VERSION 5.7 ;
DIVIDERCHAR "/" ;
BUSBITCHARS "[]" ;

VERSION 5.7 ;

BUSBITCHARS "[]" ;
DIVIDERCHAR "/" ;

UNITS
  TIME NANOSECONDS 1 ;
  CAPACITANCE PICOFARADS 1 ;
  RESISTANCE OHMS 1 ;
  DATABASE MICRONS 1000 ;
END UNITS

MANUFACTURINGGRID 0.005 ;

PROPERTYDEFINITIONS
  LAYER LEF58_TYPE STRING ;
END PROPERTYDEFINITIONS

# High density, single height
SITE obssite
  SYMMETRY Y ;
  CLASS CORE ;
  SIZE 0.2 BY 3.2 ;
END obssite


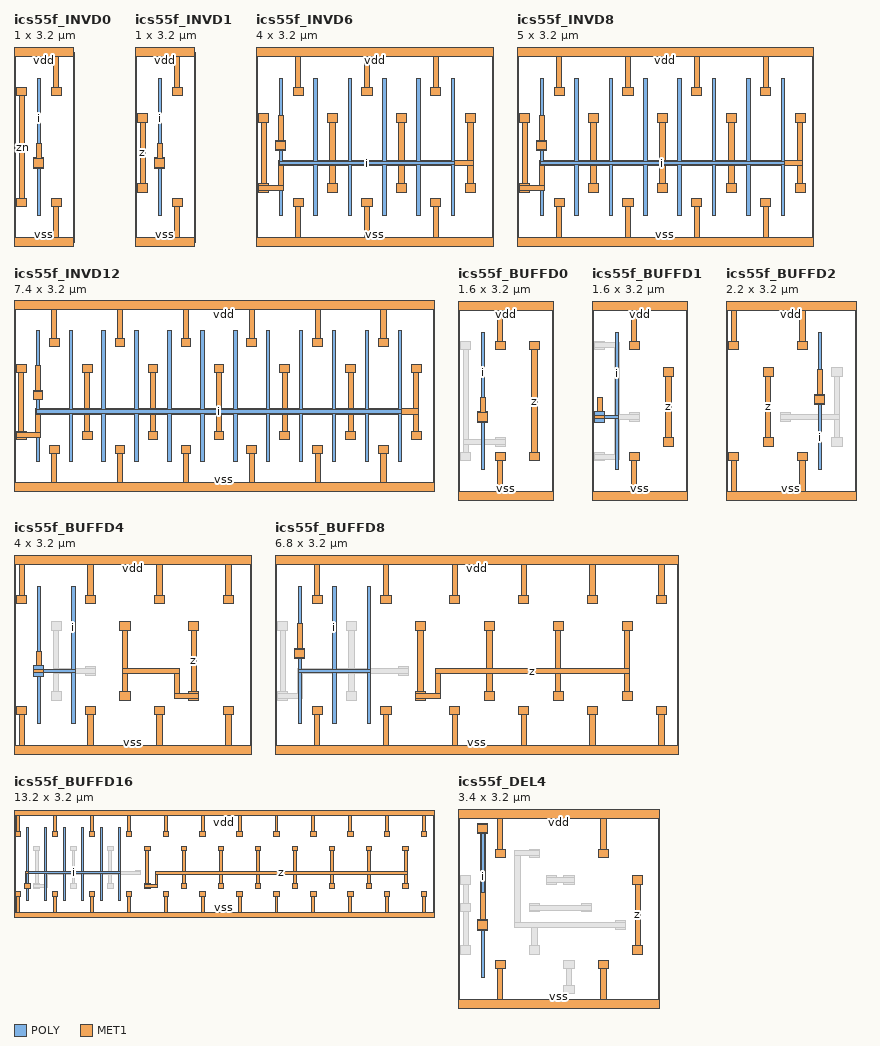
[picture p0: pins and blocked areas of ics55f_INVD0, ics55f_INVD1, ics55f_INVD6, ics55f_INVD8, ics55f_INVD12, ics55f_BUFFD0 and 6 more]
MACRO ics55f_INVD0
  CLASS CORE ;
  FOREIGN ics55f_INVD0 ;
  ORIGIN 0.000 0.000 ;
  SIZE 1.000 BY 3.200 ;
  SYMMETRY X Y R90 ;
  SITE obssite ;
  PIN i
    DIRECTION INPUT ;
    USE SIGNAL ;
    ANTENNAGATEAREA 0.030000 ;
    PORT
      LAYER POLY ;
        RECT 0.390 0.445 0.450 1.245 ;
        RECT 0.335 1.245 0.505 1.415 ;
        RECT 0.390 1.415 0.450 2.755 ;
      LAYER MET1 ;
        RECT 0.335 1.260 0.505 1.400 ;
        RECT 0.375 1.400 0.465 1.665 ;
    END
  END i
  PIN vdd
    DIRECTION INOUT ;
    USE POWER ;
    SHAPE ABUTMENT ;
    PORT
      LAYER MET1 ;
        RECT 0.625 2.470 0.795 2.610 ;
        RECT 0.665 2.610 0.755 3.120 ;
        RECT 0.000 3.120 1.000 3.280 ;
    END
  END vdd
  PIN vss
    DIRECTION INOUT ;
    USE GROUND ;
    SHAPE ABUTMENT ;
    PORT
      LAYER MET1 ;
        RECT 0.000 -0.080 1.000 0.080 ;
        RECT 0.665 0.080 0.755 0.590 ;
        RECT 0.625 0.590 0.795 0.730 ;
    END
  END vss
  PIN zn
    DIRECTION OUTPUT ;
    USE SIGNAL ;
    ANTENNADIFFAREA 0.167500 ;
    PORT
      LAYER MET1 ;
        RECT 0.045 0.590 0.215 0.730 ;
        RECT 0.085 0.730 0.175 2.470 ;
        RECT 0.045 2.470 0.215 2.610 ;
    END
  END zn
END ics55f_INVD0

MACRO ics55f_INVD1
  CLASS CORE ;
  FOREIGN ics55f_INVD1 ;
  ORIGIN 0.000 0.000 ;
  SIZE 1.000 BY 3.200 ;
  SYMMETRY X Y R90 ;
  SITE obssite ;
  PIN z
    DIRECTION OUTPUT ;
    USE SIGNAL ;
    ANTENNADIFFAREA 0.335000 ;
    PORT
      LAYER MET1 ;
        RECT 0.045 0.840 0.215 0.980 ;
        RECT 0.085 0.980 0.175 2.020 ;
        RECT 0.045 2.020 0.215 2.160 ;
    END
  END z
  PIN vdd
    DIRECTION INOUT ;
    USE POWER ;
    SHAPE ABUTMENT ;
    PORT
      LAYER MET1 ;
        RECT 0.625 2.470 0.795 2.610 ;
        RECT 0.665 2.610 0.755 3.120 ;
        RECT 0.000 3.120 1.000 3.280 ;
    END
  END vdd
  PIN vss
    DIRECTION INOUT ;
    USE GROUND ;
    SHAPE ABUTMENT ;
    PORT
      LAYER MET1 ;
        RECT 0.000 -0.080 1.000 0.080 ;
        RECT 0.665 0.080 0.755 0.590 ;
        RECT 0.625 0.590 0.795 0.730 ;
    END
  END vss
  PIN i
    DIRECTION INPUT ;
    USE SIGNAL ;
    ANTENNAGATEAREA 0.060000 ;
    PORT
      LAYER POLY ;
        RECT 0.390 0.445 0.450 1.245 ;
        RECT 0.335 1.245 0.505 1.415 ;
        RECT 0.390 1.415 0.450 2.755 ;
      LAYER MET1 ;
        RECT 0.335 1.260 0.505 1.400 ;
        RECT 0.375 1.400 0.465 1.665 ;
    END
  END i
END ics55f_INVD1

MACRO ics55f_INVD6
  CLASS CORE ;
  FOREIGN ics55f_INVD6 ;
  ORIGIN 0.000 0.000 ;
  SIZE 4.000 BY 3.200 ;
  SYMMETRY X Y R90 ;
  SITE obssite ;
  PIN i
    DIRECTION INPUT ;
    USE SIGNAL ;
    ANTENNAGATEAREA 0.360000 ;
    PORT
      LAYER POLY ;
        RECT 0.390 0.445 0.450 1.300 ;
        RECT 0.970 0.445 1.030 1.300 ;
        RECT 1.550 0.445 1.610 1.300 ;
        RECT 2.130 0.445 2.190 1.300 ;
        RECT 2.710 0.445 2.770 1.300 ;
        RECT 3.290 0.445 3.350 1.300 ;
        RECT 0.390 1.300 3.350 1.360 ;
        RECT 0.390 1.360 0.450 1.535 ;
        RECT 0.970 1.360 1.030 2.755 ;
        RECT 1.550 1.360 1.610 2.755 ;
        RECT 2.130 1.360 2.190 2.755 ;
        RECT 2.710 1.360 2.770 2.755 ;
        RECT 3.290 1.360 3.350 2.755 ;
        RECT 0.335 1.535 0.505 1.705 ;
        RECT 0.390 1.705 0.450 2.755 ;
      LAYER MET1 ;
        RECT 0.335 1.550 0.505 1.690 ;
        RECT 0.375 1.690 0.465 2.135 ;
    END
  END i
  PIN vdd
    DIRECTION INOUT ;
    USE POWER ;
    SHAPE ABUTMENT ;
    PORT
      LAYER MET1 ;
        RECT 0.625 2.470 0.795 2.610 ;
        RECT 1.785 2.470 1.955 2.610 ;
        RECT 2.945 2.470 3.115 2.610 ;
        RECT 0.665 2.610 0.755 3.120 ;
        RECT 1.825 2.610 1.915 3.120 ;
        RECT 2.985 2.610 3.075 3.120 ;
        RECT 0.000 3.120 4.000 3.280 ;
    END
  END vdd
  PIN vss
    DIRECTION INOUT ;
    USE GROUND ;
    SHAPE ABUTMENT ;
    PORT
      LAYER MET1 ;
        RECT 0.000 -0.080 4.000 0.080 ;
        RECT 0.665 0.080 0.755 0.590 ;
        RECT 1.825 0.080 1.915 0.590 ;
        RECT 2.985 0.080 3.075 0.590 ;
        RECT 0.625 0.590 0.795 0.730 ;
        RECT 1.785 0.590 1.955 0.730 ;
        RECT 2.945 0.590 3.115 0.730 ;
    END
  END vss
  PIN zn
    DIRECTION OUTPUT ;
    USE SIGNAL ;
    ANTENNADIFFAREA 1.710000 ;
    PORT
      LAYER MET1 ;
        RECT 0.045 0.840 0.215 0.865 ;
        RECT 1.205 0.840 1.375 0.980 ;
        RECT 2.365 0.840 2.535 0.980 ;
        RECT 3.525 0.840 3.695 0.980 ;
        RECT 0.045 0.865 0.465 0.955 ;
        RECT 0.045 0.955 0.215 0.980 ;
        RECT 0.375 0.955 0.465 1.285 ;
        RECT 0.085 0.980 0.175 2.020 ;
        RECT 1.245 0.980 1.335 1.285 ;
        RECT 2.405 0.980 2.495 1.285 ;
        RECT 3.565 0.980 3.655 1.285 ;
        RECT 0.375 1.285 3.655 1.375 ;
        RECT 1.245 1.375 1.335 2.020 ;
        RECT 2.405 1.375 2.495 2.020 ;
        RECT 3.565 1.375 3.655 2.020 ;
        RECT 0.045 2.020 0.215 2.160 ;
        RECT 1.205 2.020 1.375 2.160 ;
        RECT 2.365 2.020 2.535 2.160 ;
        RECT 3.525 2.020 3.695 2.160 ;
    END
  END zn
END ics55f_INVD6

MACRO ics55f_INVD8
  CLASS CORE ;
  FOREIGN ics55f_INVD8 ;
  ORIGIN 0.000 0.000 ;
  SIZE 5.000 BY 3.200 ;
  SYMMETRY X Y R90 ;
  SITE obssite ;
  PIN i
    DIRECTION INPUT ;
    USE SIGNAL ;
    ANTENNAGATEAREA 0.480000 ;
    PORT
      LAYER POLY ;
        RECT 0.390 0.445 0.450 1.300 ;
        RECT 0.970 0.445 1.030 1.300 ;
        RECT 1.550 0.445 1.610 1.300 ;
        RECT 2.130 0.445 2.190 1.300 ;
        RECT 2.710 0.445 2.770 1.300 ;
        RECT 3.290 0.445 3.350 1.300 ;
        RECT 3.870 0.445 3.930 1.300 ;
        RECT 4.450 0.445 4.510 1.300 ;
        RECT 0.390 1.300 4.510 1.360 ;
        RECT 0.390 1.360 0.450 1.535 ;
        RECT 0.970 1.360 1.030 2.755 ;
        RECT 1.550 1.360 1.610 2.755 ;
        RECT 2.130 1.360 2.190 2.755 ;
        RECT 2.710 1.360 2.770 2.755 ;
        RECT 3.290 1.360 3.350 2.755 ;
        RECT 3.870 1.360 3.930 2.755 ;
        RECT 4.450 1.360 4.510 2.755 ;
        RECT 0.335 1.535 0.505 1.705 ;
        RECT 0.390 1.705 0.450 2.755 ;
      LAYER MET1 ;
        RECT 0.335 1.550 0.505 1.690 ;
        RECT 0.375 1.690 0.465 2.135 ;
    END
  END i
  PIN vdd
    DIRECTION INOUT ;
    USE POWER ;
    SHAPE ABUTMENT ;
    PORT
      LAYER MET1 ;
        RECT 0.625 2.470 0.795 2.610 ;
        RECT 1.785 2.470 1.955 2.610 ;
        RECT 2.945 2.470 3.115 2.610 ;
        RECT 4.105 2.470 4.275 2.610 ;
        RECT 0.665 2.610 0.755 3.120 ;
        RECT 1.825 2.610 1.915 3.120 ;
        RECT 2.985 2.610 3.075 3.120 ;
        RECT 4.145 2.610 4.235 3.120 ;
        RECT 0.000 3.120 5.000 3.280 ;
    END
  END vdd
  PIN vss
    DIRECTION INOUT ;
    USE GROUND ;
    SHAPE ABUTMENT ;
    PORT
      LAYER MET1 ;
        RECT 0.000 -0.080 5.000 0.080 ;
        RECT 0.665 0.080 0.755 0.590 ;
        RECT 1.825 0.080 1.915 0.590 ;
        RECT 2.985 0.080 3.075 0.590 ;
        RECT 4.145 0.080 4.235 0.590 ;
        RECT 0.625 0.590 0.795 0.730 ;
        RECT 1.785 0.590 1.955 0.730 ;
        RECT 2.945 0.590 3.115 0.730 ;
        RECT 4.105 0.590 4.275 0.730 ;
    END
  END vss
  PIN zn
    DIRECTION OUTPUT ;
    USE SIGNAL ;
    ANTENNADIFFAREA 2.230000 ;
    PORT
      LAYER MET1 ;
        RECT 0.045 0.840 0.215 0.865 ;
        RECT 1.205 0.840 1.375 0.980 ;
        RECT 2.365 0.840 2.535 0.980 ;
        RECT 3.525 0.840 3.695 0.980 ;
        RECT 4.685 0.840 4.855 0.980 ;
        RECT 0.045 0.865 0.465 0.955 ;
        RECT 0.045 0.955 0.215 0.980 ;
        RECT 0.375 0.955 0.465 1.285 ;
        RECT 0.085 0.980 0.175 2.020 ;
        RECT 1.245 0.980 1.335 1.285 ;
        RECT 2.405 0.980 2.495 1.285 ;
        RECT 3.565 0.980 3.655 1.285 ;
        RECT 4.725 0.980 4.815 1.285 ;
        RECT 0.375 1.285 4.815 1.375 ;
        RECT 1.245 1.375 1.335 2.020 ;
        RECT 2.405 1.375 2.495 2.020 ;
        RECT 3.565 1.375 3.655 2.020 ;
        RECT 4.725 1.375 4.815 2.020 ;
        RECT 0.045 2.020 0.215 2.160 ;
        RECT 1.205 2.020 1.375 2.160 ;
        RECT 2.365 2.020 2.535 2.160 ;
        RECT 3.525 2.020 3.695 2.160 ;
        RECT 4.685 2.020 4.855 2.160 ;
    END
  END zn
END ics55f_INVD8

MACRO ics55f_INVD12
  CLASS CORE ;
  FOREIGN ics55f_INVD12 ;
  ORIGIN 0.000 0.000 ;
  SIZE 7.400 BY 3.200 ;
  SYMMETRY X Y R90 ;
  SITE obssite ;
  PIN i
    DIRECTION INPUT ;
    USE SIGNAL ;
    ANTENNAGATEAREA 0.720000 ;
    PORT
      LAYER POLY ;
        RECT 0.390 0.445 0.450 1.300 ;
        RECT 0.970 0.445 1.030 1.300 ;
        RECT 1.550 0.445 1.610 1.300 ;
        RECT 2.130 0.445 2.190 1.300 ;
        RECT 2.710 0.445 2.770 1.300 ;
        RECT 3.290 0.445 3.350 1.300 ;
        RECT 3.870 0.445 3.930 1.300 ;
        RECT 4.450 0.445 4.510 1.300 ;
        RECT 5.030 0.445 5.090 1.300 ;
        RECT 5.610 0.445 5.670 1.300 ;
        RECT 6.190 0.445 6.250 1.300 ;
        RECT 6.770 0.445 6.830 1.300 ;
        RECT 0.390 1.300 6.830 1.360 ;
        RECT 0.390 1.360 0.450 1.535 ;
        RECT 0.970 1.360 1.030 2.755 ;
        RECT 1.550 1.360 1.610 2.755 ;
        RECT 2.130 1.360 2.190 2.755 ;
        RECT 2.710 1.360 2.770 2.755 ;
        RECT 3.290 1.360 3.350 2.755 ;
        RECT 3.870 1.360 3.930 2.755 ;
        RECT 4.450 1.360 4.510 2.755 ;
        RECT 5.030 1.360 5.090 2.755 ;
        RECT 5.610 1.360 5.670 2.755 ;
        RECT 6.190 1.360 6.250 2.755 ;
        RECT 6.770 1.360 6.830 2.755 ;
        RECT 0.335 1.535 0.505 1.705 ;
        RECT 0.390 1.705 0.450 2.755 ;
      LAYER MET1 ;
        RECT 0.335 1.550 0.505 1.690 ;
        RECT 0.375 1.690 0.465 2.135 ;
    END
  END i
  PIN vdd
    DIRECTION INOUT ;
    USE POWER ;
    SHAPE ABUTMENT ;
    PORT
      LAYER MET1 ;
        RECT 0.625 2.470 0.795 2.610 ;
        RECT 1.785 2.470 1.955 2.610 ;
        RECT 2.945 2.470 3.115 2.610 ;
        RECT 4.105 2.470 4.275 2.610 ;
        RECT 5.265 2.470 5.435 2.610 ;
        RECT 6.425 2.470 6.595 2.610 ;
        RECT 0.665 2.610 0.755 3.120 ;
        RECT 1.825 2.610 1.915 3.120 ;
        RECT 2.985 2.610 3.075 3.120 ;
        RECT 4.145 2.610 4.235 3.120 ;
        RECT 5.305 2.610 5.395 3.120 ;
        RECT 6.465 2.610 6.555 3.120 ;
        RECT 0.000 3.120 7.400 3.280 ;
    END
  END vdd
  PIN vss
    DIRECTION INOUT ;
    USE GROUND ;
    SHAPE ABUTMENT ;
    PORT
      LAYER MET1 ;
        RECT 0.000 -0.080 7.400 0.080 ;
        RECT 0.665 0.080 0.755 0.590 ;
        RECT 1.825 0.080 1.915 0.590 ;
        RECT 2.985 0.080 3.075 0.590 ;
        RECT 4.145 0.080 4.235 0.590 ;
        RECT 5.305 0.080 5.395 0.590 ;
        RECT 6.465 0.080 6.555 0.590 ;
        RECT 0.625 0.590 0.795 0.730 ;
        RECT 1.785 0.590 1.955 0.730 ;
        RECT 2.945 0.590 3.115 0.730 ;
        RECT 4.105 0.590 4.275 0.730 ;
        RECT 5.265 0.590 5.435 0.730 ;
        RECT 6.425 0.590 6.595 0.730 ;
    END
  END vss
  PIN zn
    DIRECTION OUTPUT ;
    USE SIGNAL ;
    ANTENNADIFFAREA 3.270000 ;
    PORT
      LAYER MET1 ;
        RECT 0.045 0.840 0.215 0.865 ;
        RECT 1.205 0.840 1.375 0.980 ;
        RECT 2.365 0.840 2.535 0.980 ;
        RECT 3.525 0.840 3.695 0.980 ;
        RECT 4.685 0.840 4.855 0.980 ;
        RECT 5.845 0.840 6.015 0.980 ;
        RECT 7.005 0.840 7.175 0.980 ;
        RECT 0.045 0.865 0.465 0.955 ;
        RECT 0.045 0.955 0.215 0.980 ;
        RECT 0.375 0.955 0.465 1.285 ;
        RECT 0.085 0.980 0.175 2.020 ;
        RECT 1.245 0.980 1.335 1.285 ;
        RECT 2.405 0.980 2.495 1.285 ;
        RECT 3.565 0.980 3.655 1.285 ;
        RECT 4.725 0.980 4.815 1.285 ;
        RECT 5.885 0.980 5.975 1.285 ;
        RECT 7.045 0.980 7.135 1.285 ;
        RECT 0.375 1.285 7.135 1.375 ;
        RECT 1.245 1.375 1.335 2.020 ;
        RECT 2.405 1.375 2.495 2.020 ;
        RECT 3.565 1.375 3.655 2.020 ;
        RECT 4.725 1.375 4.815 2.020 ;
        RECT 5.885 1.375 5.975 2.020 ;
        RECT 7.045 1.375 7.135 2.020 ;
        RECT 0.045 2.020 0.215 2.160 ;
        RECT 1.205 2.020 1.375 2.160 ;
        RECT 2.365 2.020 2.535 2.160 ;
        RECT 3.525 2.020 3.695 2.160 ;
        RECT 4.685 2.020 4.855 2.160 ;
        RECT 5.845 2.020 6.015 2.160 ;
        RECT 7.005 2.020 7.175 2.160 ;
    END
  END zn
END ics55f_INVD12

MACRO ics55f_BUFFD0
  CLASS CORE ;
  FOREIGN ics55f_BUFFD0 ;
  ORIGIN 0.000 0.000 ;
  SIZE 1.600 BY 3.200 ;
  SYMMETRY X Y R90 ;
  SITE obssite ;
  PIN i
    DIRECTION INPUT ;
    USE SIGNAL ;
    ANTENNAGATEAREA 0.018900 ;
    PORT
      LAYER POLY ;
        RECT 0.390 0.445 0.450 1.245 ;
        RECT 0.335 1.245 0.505 1.415 ;
        RECT 0.390 1.415 0.450 2.755 ;
      LAYER MET1 ;
        RECT 0.335 1.260 0.505 1.400 ;
        RECT 0.375 1.400 0.465 1.665 ;
    END
  END i
  PIN vdd
    DIRECTION INOUT ;
    USE POWER ;
    SHAPE ABUTMENT ;
    PORT
      LAYER MET1 ;
        RECT 0.625 2.470 0.795 2.610 ;
        RECT 0.665 2.610 0.755 3.120 ;
        RECT 0.000 3.120 1.600 3.280 ;
    END
  END vdd
  PIN vss
    DIRECTION INOUT ;
    USE GROUND ;
    SHAPE ABUTMENT ;
    PORT
      LAYER MET1 ;
        RECT 0.000 -0.080 1.600 0.080 ;
        RECT 0.665 0.080 0.755 0.590 ;
        RECT 0.625 0.590 0.795 0.730 ;
    END
  END vss
  PIN z
    DIRECTION OUTPUT ;
    USE SIGNAL ;
    ANTENNADIFFAREA 0.147225 ;
    PORT
      LAYER MET1 ;
        RECT 1.205 0.590 1.375 0.730 ;
        RECT 1.245 0.730 1.335 2.470 ;
        RECT 1.205 2.470 1.375 2.610 ;
    END
  END z
  OBS
    LAYER MET1 ;
      RECT 0.045 0.590 0.215 0.730 ;
      RECT 0.085 0.730 0.175 0.865 ;
      RECT 0.625 0.840 0.795 0.865 ;
      RECT 0.085 0.865 0.795 0.955 ;
      RECT 0.085 0.955 0.175 2.470 ;
      RECT 0.625 0.955 0.795 0.980 ;
      RECT 0.045 2.470 0.215 2.610 ;
  END
END ics55f_BUFFD0

MACRO ics55f_BUFFD1
  CLASS CORE ;
  FOREIGN ics55f_BUFFD1 ;
  ORIGIN 0.000 0.000 ;
  SIZE 1.600 BY 3.200 ;
  SYMMETRY X Y R90 ;
  SITE obssite ;
  PIN i
    DIRECTION INPUT ;
    USE SIGNAL ;
    ANTENNAGATEAREA 0.030000 ;
    PORT
      LAYER POLY ;
        RECT 0.390 0.445 0.450 1.300 ;
        RECT 0.045 1.245 0.215 1.300 ;
        RECT 0.045 1.300 0.450 1.360 ;
        RECT 0.045 1.360 0.215 1.415 ;
        RECT 0.390 1.360 0.450 2.755 ;
      LAYER MET1 ;
        RECT 0.045 1.260 0.215 1.400 ;
        RECT 0.085 1.400 0.175 1.665 ;
    END
  END i
  PIN vdd
    DIRECTION INOUT ;
    USE POWER ;
    SHAPE ABUTMENT ;
    PORT
      LAYER MET1 ;
        RECT 0.625 2.470 0.795 2.610 ;
        RECT 0.665 2.610 0.755 3.120 ;
        RECT 0.000 3.120 1.600 3.280 ;
    END
  END vdd
  PIN vss
    DIRECTION INOUT ;
    USE GROUND ;
    SHAPE ABUTMENT ;
    PORT
      LAYER MET1 ;
        RECT 0.000 -0.080 1.600 0.080 ;
        RECT 0.665 0.080 0.755 0.590 ;
        RECT 0.625 0.590 0.795 0.730 ;
    END
  END vss
  PIN z
    DIRECTION OUTPUT ;
    USE SIGNAL ;
    ANTENNADIFFAREA 0.335000 ;
    PORT
      LAYER MET1 ;
        RECT 1.205 0.840 1.375 0.980 ;
        RECT 1.245 0.980 1.335 2.020 ;
        RECT 1.205 2.020 1.375 2.160 ;
    END
  END z
  OBS
    LAYER MET1 ;
      RECT 0.045 0.590 0.215 0.615 ;
      RECT 0.045 0.615 0.465 0.705 ;
      RECT 0.045 0.705 0.215 0.730 ;
      RECT 0.375 0.705 0.465 1.285 ;
      RECT 0.625 1.260 0.795 1.285 ;
      RECT 0.375 1.285 0.795 1.375 ;
      RECT 0.375 1.375 0.465 2.495 ;
      RECT 0.625 1.375 0.795 1.400 ;
      RECT 0.045 2.470 0.215 2.495 ;
      RECT 0.045 2.495 0.465 2.585 ;
      RECT 0.045 2.585 0.215 2.610 ;
  END
END ics55f_BUFFD1

MACRO ics55f_BUFFD2
  CLASS CORE ;
  FOREIGN ics55f_BUFFD2 ;
  ORIGIN 0.000 0.000 ;
  SIZE 2.200 BY 3.200 ;
  SYMMETRY X Y R90 ;
  SITE obssite ;
  PIN i
    DIRECTION INPUT ;
    USE SIGNAL ;
    ANTENNAGATEAREA 0.060000 ;
    PORT
      LAYER POLY ;
        RECT 1.550 0.445 1.610 1.535 ;
        RECT 1.495 1.535 1.665 1.705 ;
        RECT 1.550 1.705 1.610 2.755 ;
      LAYER MET1 ;
        RECT 1.495 1.550 1.665 1.690 ;
        RECT 1.535 1.690 1.625 2.135 ;
    END
  END i
  PIN vdd
    DIRECTION INOUT ;
    USE POWER ;
    SHAPE ABUTMENT ;
    PORT
      LAYER MET1 ;
        RECT 0.045 2.470 0.215 2.610 ;
        RECT 1.205 2.470 1.375 2.610 ;
        RECT 0.085 2.610 0.175 3.120 ;
        RECT 1.245 2.610 1.335 3.120 ;
        RECT 0.000 3.120 2.200 3.280 ;
    END
  END vdd
  PIN vss
    DIRECTION INOUT ;
    USE GROUND ;
    SHAPE ABUTMENT ;
    PORT
      LAYER MET1 ;
        RECT 0.000 -0.080 2.200 0.080 ;
        RECT 0.085 0.080 0.175 0.590 ;
        RECT 1.245 0.080 1.335 0.590 ;
        RECT 0.045 0.590 0.215 0.730 ;
        RECT 1.205 0.590 1.375 0.730 ;
    END
  END vss
  PIN z
    DIRECTION OUTPUT ;
    USE SIGNAL ;
    ANTENNADIFFAREA 0.520000 ;
    PORT
      LAYER MET1 ;
        RECT 0.625 0.840 0.795 0.980 ;
        RECT 0.665 0.980 0.755 2.020 ;
        RECT 0.625 2.020 0.795 2.160 ;
    END
  END z
  OBS
    LAYER MET1 ;
      RECT 1.785 0.840 1.955 0.980 ;
      RECT 1.825 0.980 1.915 1.285 ;
      RECT 0.915 1.260 1.085 1.285 ;
      RECT 0.915 1.285 1.915 1.375 ;
      RECT 0.915 1.375 1.085 1.400 ;
      RECT 1.825 1.375 1.915 2.020 ;
      RECT 1.785 2.020 1.955 2.160 ;
  END
END ics55f_BUFFD2

MACRO ics55f_BUFFD4
  CLASS CORE ;
  FOREIGN ics55f_BUFFD4 ;
  ORIGIN 0.000 0.000 ;
  SIZE 4.000 BY 3.200 ;
  SYMMETRY X Y R90 ;
  SITE obssite ;
  PIN i
    DIRECTION INPUT ;
    USE SIGNAL ;
    ANTENNAGATEAREA 0.120000 ;
    PORT
      LAYER POLY ;
        RECT 0.390 0.445 0.450 1.245 ;
        RECT 0.970 0.445 1.030 1.300 ;
        RECT 0.335 1.245 0.505 1.300 ;
        RECT 0.335 1.300 1.030 1.360 ;
        RECT 0.335 1.360 0.505 1.415 ;
        RECT 0.970 1.360 1.030 2.755 ;
        RECT 0.390 1.415 0.450 2.755 ;
      LAYER MET1 ;
        RECT 0.335 1.260 0.505 1.400 ;
        RECT 0.375 1.400 0.465 1.665 ;
    END
  END i
  PIN vdd
    DIRECTION INOUT ;
    USE POWER ;
    SHAPE ABUTMENT ;
    PORT
      LAYER MET1 ;
        RECT 0.045 2.470 0.215 2.610 ;
        RECT 1.205 2.470 1.375 2.610 ;
        RECT 2.365 2.470 2.535 2.610 ;
        RECT 3.525 2.470 3.695 2.610 ;
        RECT 0.085 2.610 0.175 3.120 ;
        RECT 1.245 2.610 1.335 3.120 ;
        RECT 2.405 2.610 2.495 3.120 ;
        RECT 3.565 2.610 3.655 3.120 ;
        RECT 0.000 3.120 4.000 3.280 ;
    END
  END vdd
  PIN vss
    DIRECTION INOUT ;
    USE GROUND ;
    SHAPE ABUTMENT ;
    PORT
      LAYER MET1 ;
        RECT 0.000 -0.080 4.000 0.080 ;
        RECT 0.085 0.080 0.175 0.590 ;
        RECT 1.245 0.080 1.335 0.590 ;
        RECT 2.405 0.080 2.495 0.590 ;
        RECT 3.565 0.080 3.655 0.590 ;
        RECT 0.045 0.590 0.215 0.730 ;
        RECT 1.205 0.590 1.375 0.730 ;
        RECT 2.365 0.590 2.535 0.730 ;
        RECT 3.525 0.590 3.695 0.730 ;
    END
  END vss
  PIN z
    DIRECTION OUTPUT ;
    USE SIGNAL ;
    ANTENNADIFFAREA 1.040000 ;
    PORT
      LAYER MET1 ;
        RECT 1.785 0.840 1.955 0.980 ;
        RECT 2.945 0.840 3.115 0.865 ;
        RECT 2.695 0.865 3.115 0.955 ;
        RECT 2.695 0.955 2.785 1.285 ;
        RECT 2.945 0.955 3.115 0.980 ;
        RECT 1.825 0.980 1.915 1.285 ;
        RECT 2.985 0.980 3.075 2.020 ;
        RECT 1.825 1.285 2.785 1.375 ;
        RECT 1.825 1.375 1.915 2.020 ;
        RECT 1.785 2.020 1.955 2.160 ;
        RECT 2.945 2.020 3.115 2.160 ;
    END
  END z
  OBS
    LAYER MET1 ;
      RECT 0.625 0.840 0.795 0.980 ;
      RECT 0.665 0.980 0.755 1.285 ;
      RECT 1.205 1.260 1.375 1.285 ;
      RECT 0.665 1.285 1.375 1.375 ;
      RECT 0.665 1.375 0.755 2.020 ;
      RECT 1.205 1.375 1.375 1.400 ;
      RECT 0.625 2.020 0.795 2.160 ;
  END
END ics55f_BUFFD4

MACRO ics55f_BUFFD8
  CLASS CORE ;
  FOREIGN ics55f_BUFFD8 ;
  ORIGIN 0.000 0.000 ;
  SIZE 6.800 BY 3.200 ;
  SYMMETRY X Y R90 ;
  SITE obssite ;
  PIN i
    DIRECTION INPUT ;
    USE SIGNAL ;
    ANTENNAGATEAREA 0.160200 ;
    PORT
      LAYER POLY ;
        RECT 0.390 0.445 0.450 1.300 ;
        RECT 0.970 0.445 1.030 1.300 ;
        RECT 1.550 0.445 1.610 1.300 ;
        RECT 0.390 1.300 1.610 1.360 ;
        RECT 0.390 1.360 0.450 1.535 ;
        RECT 0.970 1.360 1.030 2.755 ;
        RECT 1.550 1.360 1.610 2.755 ;
        RECT 0.335 1.535 0.505 1.705 ;
        RECT 0.390 1.705 0.450 2.755 ;
      LAYER MET1 ;
        RECT 0.335 1.550 0.505 1.690 ;
        RECT 0.375 1.690 0.465 2.135 ;
    END
  END i
  PIN vdd
    DIRECTION INOUT ;
    USE POWER ;
    SHAPE ABUTMENT ;
    PORT
      LAYER MET1 ;
        RECT 0.625 2.470 0.795 2.610 ;
        RECT 1.785 2.470 1.955 2.610 ;
        RECT 2.945 2.470 3.115 2.610 ;
        RECT 4.105 2.470 4.275 2.610 ;
        RECT 5.265 2.470 5.435 2.610 ;
        RECT 6.425 2.470 6.595 2.610 ;
        RECT 0.665 2.610 0.755 3.120 ;
        RECT 1.825 2.610 1.915 3.120 ;
        RECT 2.985 2.610 3.075 3.120 ;
        RECT 4.145 2.610 4.235 3.120 ;
        RECT 5.305 2.610 5.395 3.120 ;
        RECT 6.465 2.610 6.555 3.120 ;
        RECT 0.000 3.120 6.800 3.280 ;
    END
  END vdd
  PIN vss
    DIRECTION INOUT ;
    USE GROUND ;
    SHAPE ABUTMENT ;
    PORT
      LAYER MET1 ;
        RECT 0.000 -0.080 6.800 0.080 ;
        RECT 0.665 0.080 0.755 0.590 ;
        RECT 1.825 0.080 1.915 0.590 ;
        RECT 2.985 0.080 3.075 0.590 ;
        RECT 4.145 0.080 4.235 0.590 ;
        RECT 5.305 0.080 5.395 0.590 ;
        RECT 6.465 0.080 6.555 0.590 ;
        RECT 0.625 0.590 0.795 0.730 ;
        RECT 1.785 0.590 1.955 0.730 ;
        RECT 2.945 0.590 3.115 0.730 ;
        RECT 4.105 0.590 4.275 0.730 ;
        RECT 5.265 0.590 5.435 0.730 ;
        RECT 6.425 0.590 6.595 0.730 ;
    END
  END vss
  PIN z
    DIRECTION OUTPUT ;
    USE SIGNAL ;
    ANTENNADIFFAREA 2.080000 ;
    PORT
      LAYER MET1 ;
        RECT 2.365 0.840 2.535 0.865 ;
        RECT 3.525 0.840 3.695 0.980 ;
        RECT 4.685 0.840 4.855 0.980 ;
        RECT 5.845 0.840 6.015 0.980 ;
        RECT 2.365 0.865 2.785 0.955 ;
        RECT 2.365 0.955 2.535 0.980 ;
        RECT 2.695 0.955 2.785 1.285 ;
        RECT 2.405 0.980 2.495 2.020 ;
        RECT 3.565 0.980 3.655 1.285 ;
        RECT 4.725 0.980 4.815 1.285 ;
        RECT 5.885 0.980 5.975 1.285 ;
        RECT 2.695 1.285 5.975 1.375 ;
        RECT 3.565 1.375 3.655 2.020 ;
        RECT 4.725 1.375 4.815 2.020 ;
        RECT 5.885 1.375 5.975 2.020 ;
        RECT 2.365 2.020 2.535 2.160 ;
        RECT 3.525 2.020 3.695 2.160 ;
        RECT 4.685 2.020 4.855 2.160 ;
        RECT 5.845 2.020 6.015 2.160 ;
    END
  END z
  OBS
    LAYER MET1 ;
      RECT 0.045 0.840 0.215 0.865 ;
      RECT 1.205 0.840 1.375 0.980 ;
      RECT 0.045 0.865 0.465 0.955 ;
      RECT 0.045 0.955 0.215 0.980 ;
      RECT 0.375 0.955 0.465 1.285 ;
      RECT 0.085 0.980 0.175 2.020 ;
      RECT 1.245 0.980 1.335 1.285 ;
      RECT 2.075 1.260 2.245 1.285 ;
      RECT 0.375 1.285 2.245 1.375 ;
      RECT 1.245 1.375 1.335 2.020 ;
      RECT 2.075 1.375 2.245 1.400 ;
      RECT 0.045 2.020 0.215 2.160 ;
      RECT 1.205 2.020 1.375 2.160 ;
  END
END ics55f_BUFFD8

MACRO ics55f_BUFFD16
  CLASS CORE ;
  FOREIGN ics55f_BUFFD16 ;
  ORIGIN 0.000 0.000 ;
  SIZE 13.200 BY 3.200 ;
  SYMMETRY X Y R90 ;
  SITE obssite ;
  PIN i
    DIRECTION INPUT ;
    USE SIGNAL ;
    ANTENNAGATEAREA 0.320400 ;
    PORT
      LAYER POLY ;
        RECT 0.390 0.445 0.450 0.825 ;
        RECT 0.970 0.445 1.030 1.300 ;
        RECT 1.550 0.445 1.610 1.300 ;
        RECT 2.130 0.445 2.190 1.300 ;
        RECT 2.710 0.445 2.770 1.300 ;
        RECT 3.290 0.445 3.350 1.300 ;
        RECT 0.335 0.825 0.505 0.995 ;
        RECT 0.390 0.995 0.450 1.300 ;
        RECT 0.390 1.300 3.350 1.360 ;
        RECT 0.390 1.360 0.450 2.755 ;
        RECT 0.970 1.360 1.030 2.755 ;
        RECT 1.550 1.360 1.610 2.755 ;
        RECT 2.130 1.360 2.190 2.755 ;
        RECT 2.710 1.360 2.770 2.755 ;
        RECT 3.290 1.360 3.350 2.755 ;
      LAYER MET1 ;
        RECT 0.335 0.840 0.505 0.980 ;
        RECT 0.375 0.980 0.465 1.375 ;
    END
  END i
  PIN vdd
    DIRECTION INOUT ;
    USE POWER ;
    SHAPE ABUTMENT ;
    PORT
      LAYER MET1 ;
        RECT 0.045 2.470 0.215 2.610 ;
        RECT 1.205 2.470 1.375 2.610 ;
        RECT 2.365 2.470 2.535 2.610 ;
        RECT 3.525 2.470 3.695 2.610 ;
        RECT 4.685 2.470 4.855 2.610 ;
        RECT 5.845 2.470 6.015 2.610 ;
        RECT 7.005 2.470 7.175 2.610 ;
        RECT 8.165 2.470 8.335 2.610 ;
        RECT 9.325 2.470 9.495 2.610 ;
        RECT 10.485 2.470 10.655 2.610 ;
        RECT 11.645 2.470 11.815 2.610 ;
        RECT 12.805 2.470 12.975 2.610 ;
        RECT 0.085 2.610 0.175 3.120 ;
        RECT 1.245 2.610 1.335 3.120 ;
        RECT 2.405 2.610 2.495 3.120 ;
        RECT 3.565 2.610 3.655 3.120 ;
        RECT 4.725 2.610 4.815 3.120 ;
        RECT 5.885 2.610 5.975 3.120 ;
        RECT 7.045 2.610 7.135 3.120 ;
        RECT 8.205 2.610 8.295 3.120 ;
        RECT 9.365 2.610 9.455 3.120 ;
        RECT 10.525 2.610 10.615 3.120 ;
        RECT 11.685 2.610 11.775 3.120 ;
        RECT 12.845 2.610 12.935 3.120 ;
        RECT 0.000 3.120 13.200 3.280 ;
    END
  END vdd
  PIN vss
    DIRECTION INOUT ;
    USE GROUND ;
    SHAPE ABUTMENT ;
    PORT
      LAYER MET1 ;
        RECT 0.000 -0.080 13.200 0.080 ;
        RECT 0.085 0.080 0.175 0.590 ;
        RECT 1.245 0.080 1.335 0.590 ;
        RECT 2.405 0.080 2.495 0.590 ;
        RECT 3.565 0.080 3.655 0.590 ;
        RECT 4.725 0.080 4.815 0.590 ;
        RECT 5.885 0.080 5.975 0.590 ;
        RECT 7.045 0.080 7.135 0.590 ;
        RECT 8.205 0.080 8.295 0.590 ;
        RECT 9.365 0.080 9.455 0.590 ;
        RECT 10.525 0.080 10.615 0.590 ;
        RECT 11.685 0.080 11.775 0.590 ;
        RECT 12.845 0.080 12.935 0.590 ;
        RECT 0.045 0.590 0.215 0.730 ;
        RECT 1.205 0.590 1.375 0.730 ;
        RECT 2.365 0.590 2.535 0.730 ;
        RECT 3.525 0.590 3.695 0.730 ;
        RECT 4.685 0.590 4.855 0.730 ;
        RECT 5.845 0.590 6.015 0.730 ;
        RECT 7.005 0.590 7.175 0.730 ;
        RECT 8.165 0.590 8.335 0.730 ;
        RECT 9.325 0.590 9.495 0.730 ;
        RECT 10.485 0.590 10.655 0.730 ;
        RECT 11.645 0.590 11.815 0.730 ;
        RECT 12.805 0.590 12.975 0.730 ;
    END
  END vss
  PIN z
    DIRECTION OUTPUT ;
    USE SIGNAL ;
    ANTENNADIFFAREA 4.160000 ;
    PORT
      LAYER MET1 ;
        RECT 4.105 0.840 4.275 0.865 ;
        RECT 5.265 0.840 5.435 0.980 ;
        RECT 6.425 0.840 6.595 0.980 ;
        RECT 7.585 0.840 7.755 0.980 ;
        RECT 8.745 0.840 8.915 0.980 ;
        RECT 9.905 0.840 10.075 0.980 ;
        RECT 11.065 0.840 11.235 0.980 ;
        RECT 12.225 0.840 12.395 0.980 ;
        RECT 4.105 0.865 4.525 0.955 ;
        RECT 4.105 0.955 4.275 0.980 ;
        RECT 4.435 0.955 4.525 1.285 ;
        RECT 4.145 0.980 4.235 2.020 ;
        RECT 5.305 0.980 5.395 1.285 ;
        RECT 6.465 0.980 6.555 1.285 ;
        RECT 7.625 0.980 7.715 1.285 ;
        RECT 8.785 0.980 8.875 1.285 ;
        RECT 9.945 0.980 10.035 1.285 ;
        RECT 11.105 0.980 11.195 1.285 ;
        RECT 12.265 0.980 12.355 1.285 ;
        RECT 4.435 1.285 12.355 1.375 ;
        RECT 5.305 1.375 5.395 2.020 ;
        RECT 6.465 1.375 6.555 2.020 ;
        RECT 7.625 1.375 7.715 2.020 ;
        RECT 8.785 1.375 8.875 2.020 ;
        RECT 9.945 1.375 10.035 2.020 ;
        RECT 11.105 1.375 11.195 2.020 ;
        RECT 12.265 1.375 12.355 2.020 ;
        RECT 4.105 2.020 4.275 2.160 ;
        RECT 5.265 2.020 5.435 2.160 ;
        RECT 6.425 2.020 6.595 2.160 ;
        RECT 7.585 2.020 7.755 2.160 ;
        RECT 8.745 2.020 8.915 2.160 ;
        RECT 9.905 2.020 10.075 2.160 ;
        RECT 11.065 2.020 11.235 2.160 ;
        RECT 12.225 2.020 12.395 2.160 ;
    END
  END z
  OBS
    LAYER MET1 ;
      RECT 0.625 0.840 0.795 0.865 ;
      RECT 1.785 0.840 1.955 0.980 ;
      RECT 2.945 0.840 3.115 0.980 ;
      RECT 0.625 0.865 1.045 0.955 ;
      RECT 0.625 0.955 0.795 0.980 ;
      RECT 0.955 0.955 1.045 1.285 ;
      RECT 0.665 0.980 0.755 2.020 ;
      RECT 1.825 0.980 1.915 1.285 ;
      RECT 2.985 0.980 3.075 1.285 ;
      RECT 3.815 1.260 3.985 1.285 ;
      RECT 0.955 1.285 3.985 1.375 ;
      RECT 1.825 1.375 1.915 2.020 ;
      RECT 2.985 1.375 3.075 2.020 ;
      RECT 3.815 1.375 3.985 1.400 ;
      RECT 0.625 2.020 0.795 2.160 ;
      RECT 1.785 2.020 1.955 2.160 ;
      RECT 2.945 2.020 3.115 2.160 ;
  END
END ics55f_BUFFD16

MACRO ics55f_DEL4
  CLASS CORE ;
  FOREIGN ics55f_DEL4 ;
  ORIGIN 0.000 0.000 ;
  SIZE 3.400 BY 3.200 ;
  SYMMETRY X Y R90 ;
  SITE obssite ;
  PIN i
    DIRECTION INPUT ;
    USE SIGNAL ;
    ANTENNAGATEAREA 0.060000 ;
    PORT
      LAYER POLY ;
        RECT 0.390 0.445 0.450 1.245 ;
        RECT 0.335 1.245 0.505 1.415 ;
        RECT 0.390 1.875 0.450 2.875 ;
        RECT 0.335 2.875 0.505 3.045 ;
      LAYER MET1 ;
        RECT 0.335 1.260 0.505 1.400 ;
        RECT 0.375 1.400 0.465 2.890 ;
        RECT 0.335 2.890 0.505 3.030 ;
    END
  END i
  PIN vdd
    DIRECTION INOUT ;
    USE POWER ;
    SHAPE ABUTMENT ;
    PORT
      LAYER MET1 ;
        RECT 0.625 2.470 0.795 2.610 ;
        RECT 2.365 2.470 2.535 2.610 ;
        RECT 0.665 2.610 0.755 3.120 ;
        RECT 2.405 2.610 2.495 3.120 ;
        RECT 0.000 3.120 3.400 3.280 ;
    END
  END vdd
  PIN vss
    DIRECTION INOUT ;
    USE GROUND ;
    SHAPE ABUTMENT ;
    PORT
      LAYER MET1 ;
        RECT 0.000 -0.080 3.400 0.080 ;
        RECT 0.665 0.080 0.755 0.590 ;
        RECT 2.405 0.080 2.495 0.590 ;
        RECT 0.625 0.590 0.795 0.730 ;
        RECT 2.365 0.590 2.535 0.730 ;
    END
  END vss
  PIN z
    DIRECTION OUTPUT ;
    USE SIGNAL ;
    ANTENNADIFFAREA 0.335000 ;
    PORT
      LAYER MET1 ;
        RECT 2.945 0.840 3.115 0.980 ;
        RECT 2.985 0.980 3.075 2.020 ;
        RECT 2.945 2.020 3.115 2.160 ;
    END
  END z
  OBS
    LAYER MET1 ;
      RECT 1.785 0.170 1.955 0.310 ;
      RECT 1.825 0.310 1.915 0.590 ;
      RECT 1.785 0.590 1.955 0.730 ;
      RECT 0.045 0.840 0.215 0.980 ;
      RECT 1.205 0.840 1.375 0.980 ;
      RECT 0.085 0.980 0.175 1.550 ;
      RECT 1.245 0.980 1.335 1.285 ;
      RECT 2.655 1.260 2.825 1.285 ;
      RECT 0.955 1.285 2.825 1.375 ;
      RECT 0.955 1.375 1.045 2.495 ;
      RECT 2.655 1.375 2.825 1.400 ;
      RECT 0.045 1.550 0.215 1.690 ;
      RECT 1.205 1.550 1.375 1.575 ;
      RECT 2.075 1.550 2.245 1.575 ;
      RECT 1.205 1.575 2.245 1.665 ;
      RECT 1.205 1.665 1.375 1.690 ;
      RECT 2.075 1.665 2.245 1.690 ;
      RECT 0.085 1.690 0.175 2.020 ;
      RECT 0.045 2.020 0.215 2.160 ;
      RECT 1.495 2.020 1.665 2.045 ;
      RECT 1.785 2.020 1.955 2.045 ;
      RECT 1.495 2.045 1.955 2.135 ;
      RECT 1.495 2.135 1.665 2.160 ;
      RECT 1.785 2.135 1.955 2.160 ;
      RECT 1.205 2.470 1.375 2.495 ;
      RECT 0.955 2.495 1.375 2.585 ;
      RECT 1.205 2.585 1.375 2.610 ;
  END
END ics55f_DEL4

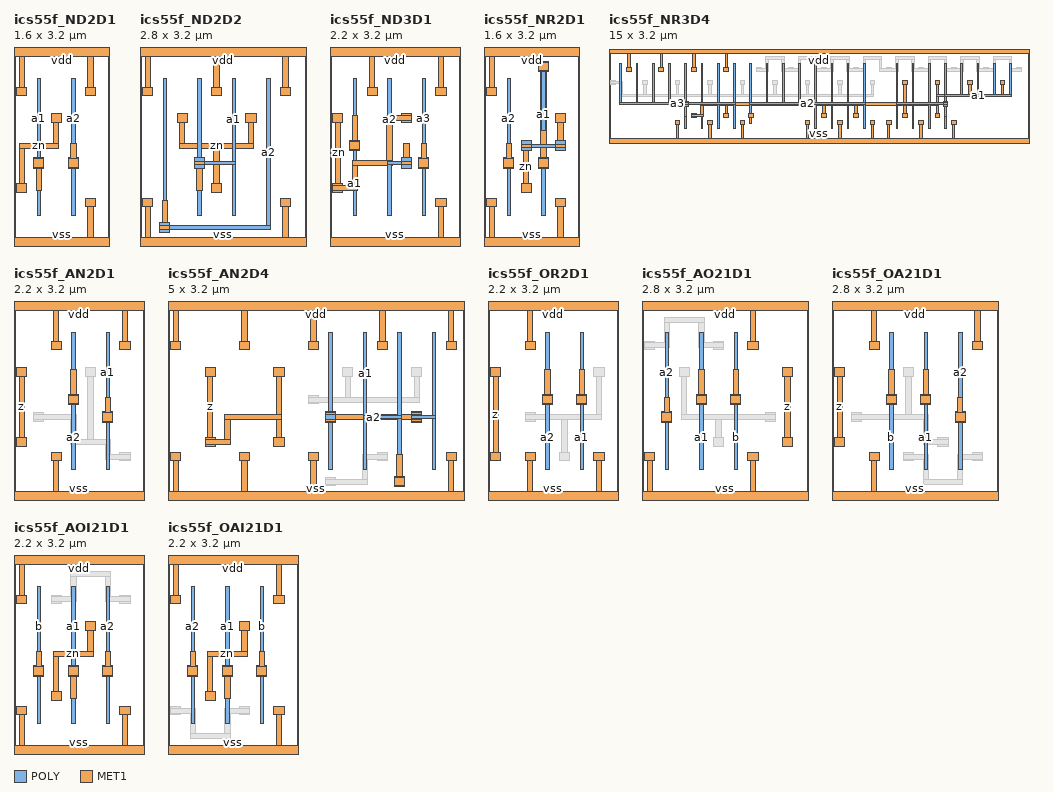
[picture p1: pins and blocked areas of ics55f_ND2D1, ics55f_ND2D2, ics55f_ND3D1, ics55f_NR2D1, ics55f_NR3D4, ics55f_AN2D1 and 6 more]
MACRO ics55f_ND2D1
  CLASS CORE ;
  FOREIGN ics55f_ND2D1 ;
  ORIGIN 0.000 0.000 ;
  SIZE 1.600 BY 3.200 ;
  SYMMETRY X Y R90 ;
  SITE obssite ;
  PIN a1
    DIRECTION INPUT ;
    USE SIGNAL ;
    ANTENNAGATEAREA 0.060000 ;
    PORT
      LAYER POLY ;
        RECT 0.390 0.445 0.450 1.245 ;
        RECT 0.335 1.245 0.505 1.415 ;
        RECT 0.390 1.415 0.450 2.755 ;
      LAYER MET1 ;
        RECT 0.375 0.865 0.465 1.260 ;
        RECT 0.335 1.260 0.505 1.400 ;
    END
  END a1
  PIN a2
    DIRECTION INPUT ;
    USE SIGNAL ;
    ANTENNAGATEAREA 0.060000 ;
    PORT
      LAYER POLY ;
        RECT 0.970 0.445 1.030 1.245 ;
        RECT 0.915 1.245 1.085 1.415 ;
        RECT 0.970 1.415 1.030 2.755 ;
      LAYER MET1 ;
        RECT 0.915 1.260 1.085 1.400 ;
        RECT 0.955 1.400 1.045 1.665 ;
    END
  END a2
  PIN vdd
    DIRECTION INOUT ;
    USE POWER ;
    SHAPE ABUTMENT ;
    PORT
      LAYER MET1 ;
        RECT 0.045 2.470 0.215 2.610 ;
        RECT 1.205 2.470 1.375 2.610 ;
        RECT 0.085 2.610 0.175 3.120 ;
        RECT 1.245 2.610 1.335 3.120 ;
        RECT 0.000 3.120 1.600 3.280 ;
    END
  END vdd
  PIN vss
    DIRECTION INOUT ;
    USE GROUND ;
    SHAPE ABUTMENT ;
    PORT
      LAYER MET1 ;
        RECT 0.000 -0.080 1.600 0.080 ;
        RECT 1.245 0.080 1.335 0.590 ;
        RECT 1.205 0.590 1.375 0.730 ;
    END
  END vss
  PIN zn
    DIRECTION OUTPUT ;
    USE SIGNAL ;
    ANTENNADIFFAREA 0.446000 ;
    PORT
      LAYER MET1 ;
        RECT 0.045 0.840 0.215 0.980 ;
        RECT 0.085 0.980 0.175 1.575 ;
        RECT 0.085 1.575 0.755 1.665 ;
        RECT 0.665 1.665 0.755 2.020 ;
        RECT 0.625 2.020 0.795 2.160 ;
    END
  END zn
END ics55f_ND2D1

MACRO ics55f_ND2D2
  CLASS CORE ;
  FOREIGN ics55f_ND2D2 ;
  ORIGIN 0.000 0.000 ;
  SIZE 2.800 BY 3.200 ;
  SYMMETRY X Y R90 ;
  SITE obssite ;
  PIN a1
    DIRECTION INPUT ;
    USE SIGNAL ;
    ANTENNAGATEAREA 0.120000 ;
    PORT
      LAYER POLY ;
        RECT 0.970 0.445 1.030 1.245 ;
        RECT 1.550 0.445 1.610 1.300 ;
        RECT 0.915 1.245 1.085 1.300 ;
        RECT 0.915 1.300 1.610 1.360 ;
        RECT 0.915 1.360 1.085 1.415 ;
        RECT 1.550 1.360 1.610 2.755 ;
        RECT 0.970 1.415 1.030 2.755 ;
      LAYER MET1 ;
        RECT 0.955 0.865 1.045 1.260 ;
        RECT 0.915 1.260 1.085 1.400 ;
    END
  END a1
  PIN a2
    DIRECTION INPUT ;
    USE SIGNAL ;
    ANTENNAGATEAREA 0.120000 ;
    PORT
      LAYER POLY ;
        RECT 0.335 0.155 0.505 0.210 ;
        RECT 0.335 0.210 2.190 0.270 ;
        RECT 0.335 0.270 0.505 0.325 ;
        RECT 2.130 0.270 2.190 2.755 ;
        RECT 0.390 0.325 0.450 2.755 ;
      LAYER MET1 ;
        RECT 0.335 0.170 0.505 0.310 ;
        RECT 0.375 0.310 0.465 0.705 ;
    END
  END a2
  PIN vdd
    DIRECTION INOUT ;
    USE POWER ;
    SHAPE ABUTMENT ;
    PORT
      LAYER MET1 ;
        RECT 0.045 2.470 0.215 2.610 ;
        RECT 1.205 2.470 1.375 2.610 ;
        RECT 2.365 2.470 2.535 2.610 ;
        RECT 0.085 2.610 0.175 3.120 ;
        RECT 1.245 2.610 1.335 3.120 ;
        RECT 2.405 2.610 2.495 3.120 ;
        RECT 0.000 3.120 2.800 3.280 ;
    END
  END vdd
  PIN vss
    DIRECTION INOUT ;
    USE GROUND ;
    SHAPE ABUTMENT ;
    PORT
      LAYER MET1 ;
        RECT 0.000 -0.080 2.800 0.080 ;
        RECT 0.085 0.080 0.175 0.590 ;
        RECT 2.405 0.080 2.495 0.590 ;
        RECT 0.045 0.590 0.215 0.730 ;
        RECT 2.365 0.590 2.535 0.730 ;
    END
  END vss
  PIN zn
    DIRECTION OUTPUT ;
    USE SIGNAL ;
    ANTENNADIFFAREA 0.832000 ;
    PORT
      LAYER MET1 ;
        RECT 1.205 0.840 1.375 0.980 ;
        RECT 1.245 0.980 1.335 1.575 ;
        RECT 0.665 1.575 1.915 1.665 ;
        RECT 0.665 1.665 0.755 2.020 ;
        RECT 1.825 1.665 1.915 2.020 ;
        RECT 0.625 2.020 0.795 2.160 ;
        RECT 1.785 2.020 1.955 2.160 ;
    END
  END zn
END ics55f_ND2D2

MACRO ics55f_ND3D1
  CLASS CORE ;
  FOREIGN ics55f_ND3D1 ;
  ORIGIN 0.000 0.000 ;
  SIZE 2.200 BY 3.200 ;
  SYMMETRY X Y R90 ;
  SITE obssite ;
  PIN a1
    DIRECTION INPUT ;
    USE SIGNAL ;
    ANTENNAGATEAREA 0.060000 ;
    PORT
      LAYER POLY ;
        RECT 0.390 0.445 0.450 1.535 ;
        RECT 0.335 1.535 0.505 1.705 ;
        RECT 0.390 1.705 0.450 2.755 ;
      LAYER MET1 ;
        RECT 0.335 1.550 0.505 1.690 ;
        RECT 0.375 1.690 0.465 2.135 ;
    END
  END a1
  PIN a2
    DIRECTION INPUT ;
    USE SIGNAL ;
    ANTENNAGATEAREA 0.060000 ;
    PORT
      LAYER POLY ;
        RECT 0.970 0.445 1.030 1.300 ;
        RECT 1.205 1.245 1.375 1.300 ;
        RECT 0.970 1.300 1.375 1.360 ;
        RECT 0.970 1.360 1.030 2.755 ;
        RECT 1.205 1.360 1.375 1.415 ;
      LAYER MET1 ;
        RECT 1.205 1.260 1.375 1.400 ;
        RECT 1.245 1.400 1.335 1.665 ;
    END
  END a2
  PIN a3
    DIRECTION INPUT ;
    USE SIGNAL ;
    ANTENNAGATEAREA 0.060000 ;
    PORT
      LAYER POLY ;
        RECT 1.550 0.445 1.610 1.245 ;
        RECT 1.495 1.245 1.665 1.415 ;
        RECT 1.550 1.415 1.610 2.755 ;
      LAYER MET1 ;
        RECT 1.495 1.260 1.665 1.400 ;
        RECT 1.535 1.400 1.625 1.665 ;
    END
  END a3
  PIN vdd
    DIRECTION INOUT ;
    USE POWER ;
    SHAPE ABUTMENT ;
    PORT
      LAYER MET1 ;
        RECT 0.625 2.470 0.795 2.610 ;
        RECT 1.785 2.470 1.955 2.610 ;
        RECT 0.665 2.610 0.755 3.120 ;
        RECT 1.825 2.610 1.915 3.120 ;
        RECT 0.000 3.120 2.200 3.280 ;
    END
  END vdd
  PIN vss
    DIRECTION INOUT ;
    USE GROUND ;
    SHAPE ABUTMENT ;
    PORT
      LAYER MET1 ;
        RECT 0.000 -0.080 2.200 0.080 ;
        RECT 1.825 0.080 1.915 0.590 ;
        RECT 1.785 0.590 1.955 0.730 ;
    END
  END vss
  PIN zn
    DIRECTION OUTPUT ;
    USE SIGNAL ;
    ANTENNADIFFAREA 0.647000 ;
    PORT
      LAYER MET1 ;
        RECT 0.045 0.840 0.215 0.865 ;
        RECT 0.045 0.865 0.465 0.955 ;
        RECT 0.045 0.955 0.215 0.980 ;
        RECT 0.375 0.955 0.465 1.285 ;
        RECT 0.085 0.980 0.175 2.020 ;
        RECT 0.375 1.285 1.045 1.375 ;
        RECT 0.955 1.375 1.045 2.045 ;
        RECT 0.045 2.020 0.215 2.160 ;
        RECT 1.205 2.020 1.375 2.045 ;
        RECT 0.955 2.045 1.375 2.135 ;
        RECT 1.205 2.135 1.375 2.160 ;
    END
  END zn
END ics55f_ND3D1

MACRO ics55f_NR2D1
  CLASS CORE ;
  FOREIGN ics55f_NR2D1 ;
  ORIGIN 0.000 0.000 ;
  SIZE 1.600 BY 3.200 ;
  SYMMETRY X Y R90 ;
  SITE obssite ;
  PIN a1
    DIRECTION INPUT ;
    USE SIGNAL ;
    ANTENNAGATEAREA 0.060000 ;
    PORT
      LAYER POLY ;
        RECT 0.970 0.445 1.030 1.245 ;
        RECT 0.915 1.245 1.085 1.415 ;
        RECT 0.970 1.875 1.030 2.875 ;
        RECT 0.915 2.875 1.085 3.045 ;
      LAYER MET1 ;
        RECT 0.915 1.260 1.085 1.400 ;
        RECT 0.955 1.400 1.045 2.890 ;
        RECT 0.915 2.890 1.085 3.030 ;
    END
  END a1
  PIN a2
    DIRECTION INPUT ;
    USE SIGNAL ;
    ANTENNAGATEAREA 0.060000 ;
    PORT
      LAYER POLY ;
        RECT 0.390 0.445 0.450 1.245 ;
        RECT 0.335 1.245 0.505 1.415 ;
        RECT 0.390 1.415 0.450 2.755 ;
      LAYER MET1 ;
        RECT 0.335 1.260 0.505 1.400 ;
        RECT 0.375 1.400 0.465 1.665 ;
    END
  END a2
  PIN vdd
    DIRECTION INOUT ;
    USE POWER ;
    SHAPE ABUTMENT ;
    PORT
      LAYER MET1 ;
        RECT 0.045 2.470 0.215 2.610 ;
        RECT 0.085 2.610 0.175 3.120 ;
        RECT 0.000 3.120 1.600 3.280 ;
    END
  END vdd
  PIN vss
    DIRECTION INOUT ;
    USE GROUND ;
    SHAPE ABUTMENT ;
    PORT
      LAYER MET1 ;
        RECT 0.000 -0.080 1.600 0.080 ;
        RECT 0.085 0.080 0.175 0.590 ;
        RECT 1.245 0.080 1.335 0.590 ;
        RECT 0.045 0.590 0.215 0.730 ;
        RECT 1.205 0.590 1.375 0.730 ;
    END
  END vss
  PIN zn
    DIRECTION OUTPUT ;
    USE SIGNAL ;
    ANTENNADIFFAREA 0.409000 ;
    PORT
      LAYER POLY ;
        RECT 0.625 1.535 0.795 1.590 ;
        RECT 1.205 1.535 1.375 1.590 ;
        RECT 0.625 1.590 1.375 1.650 ;
        RECT 0.625 1.650 0.795 1.705 ;
        RECT 1.205 1.650 1.375 1.705 ;
      LAYER MET1 ;
        RECT 0.625 0.840 0.795 0.980 ;
        RECT 0.665 0.980 0.755 1.550 ;
        RECT 0.625 1.550 0.795 1.690 ;
        RECT 1.205 1.550 1.375 1.690 ;
        RECT 1.245 1.690 1.335 2.020 ;
        RECT 1.205 2.020 1.375 2.160 ;
    END
  END zn
END ics55f_NR2D1

MACRO ics55f_NR3D4
  CLASS CORE ;
  FOREIGN ics55f_NR3D4 ;
  ORIGIN 0.000 0.000 ;
  SIZE 15.000 BY 3.200 ;
  SYMMETRY X Y R90 ;
  SITE obssite ;
  PIN a1
    DIRECTION INPUT ;
    USE SIGNAL ;
    ANTENNAGATEAREA 0.384000 ;
    PORT
      LAYER POLY ;
        RECT 10.250 0.445 10.310 1.300 ;
        RECT 10.830 0.445 10.890 1.300 ;
        RECT 11.410 0.445 11.470 1.300 ;
        RECT 11.990 0.445 12.050 1.245 ;
        RECT 11.935 1.245 12.105 1.300 ;
        RECT 10.250 1.300 12.105 1.360 ;
        RECT 10.250 1.360 10.310 2.755 ;
        RECT 10.830 1.360 10.890 2.755 ;
        RECT 11.410 1.360 11.470 2.755 ;
        RECT 11.935 1.360 12.105 1.415 ;
        RECT 11.990 1.415 12.050 1.590 ;
        RECT 11.990 1.590 14.370 1.650 ;
        RECT 11.990 1.650 12.050 2.755 ;
        RECT 12.570 1.650 12.630 2.755 ;
        RECT 13.150 1.650 13.210 2.755 ;
        RECT 13.730 1.650 13.790 2.755 ;
        RECT 14.310 1.650 14.370 2.755 ;
      LAYER MET1 ;
        RECT 11.975 0.865 12.065 1.260 ;
        RECT 11.935 1.260 12.105 1.400 ;
    END
  END a1
  PIN a2
    DIRECTION INPUT ;
    USE SIGNAL ;
    ANTENNAGATEAREA 0.384000 ;
    PORT
      LAYER POLY ;
        RECT 7.350 0.445 7.410 1.300 ;
        RECT 7.930 0.445 7.990 1.300 ;
        RECT 8.510 0.445 8.570 1.300 ;
        RECT 9.090 0.445 9.150 1.300 ;
        RECT 4.975 0.825 5.145 0.995 ;
        RECT 5.030 0.995 5.090 1.300 ;
        RECT 5.030 1.300 9.150 1.360 ;
        RECT 5.030 1.360 5.090 2.755 ;
        RECT 5.610 1.360 5.670 2.755 ;
        RECT 6.190 1.360 6.250 2.755 ;
        RECT 6.770 1.360 6.830 2.755 ;
        RECT 7.350 1.360 7.410 2.755 ;
        RECT 7.930 1.360 7.990 2.755 ;
        RECT 8.510 1.360 8.570 2.755 ;
        RECT 9.090 1.360 9.150 2.755 ;
      LAYER MET1 ;
        RECT 5.015 0.615 5.105 0.840 ;
        RECT 4.975 0.840 5.145 0.980 ;
    END
  END a2
  PIN a3
    DIRECTION INPUT ;
    USE SIGNAL ;
    ANTENNAGATEAREA 0.384000 ;
    PORT
      LAYER POLY ;
        RECT 2.710 0.445 2.770 1.245 ;
        RECT 3.290 0.445 3.350 1.300 ;
        RECT 3.870 0.445 3.930 1.300 ;
        RECT 4.450 0.445 4.510 1.300 ;
        RECT 2.655 1.245 2.825 1.300 ;
        RECT 0.390 1.300 4.510 1.360 ;
        RECT 0.390 1.360 0.450 2.755 ;
        RECT 0.970 1.360 1.030 2.755 ;
        RECT 1.550 1.360 1.610 2.755 ;
        RECT 2.130 1.360 2.190 2.755 ;
        RECT 2.655 1.360 2.825 1.415 ;
        RECT 3.290 1.360 3.350 2.755 ;
        RECT 3.870 1.360 3.930 2.755 ;
        RECT 4.450 1.360 4.510 2.755 ;
        RECT 2.710 1.415 2.770 2.755 ;
      LAYER MET1 ;
        RECT 2.695 0.865 2.785 1.260 ;
        RECT 2.655 1.260 2.825 1.400 ;
    END
  END a3
  PIN vdd
    DIRECTION INOUT ;
    USE POWER ;
    SHAPE ABUTMENT ;
    PORT
      LAYER MET1 ;
        RECT 0.625 2.470 0.795 2.610 ;
        RECT 1.785 2.470 1.955 2.610 ;
        RECT 2.945 2.470 3.115 2.610 ;
        RECT 4.105 2.470 4.275 2.610 ;
        RECT 0.665 2.610 0.755 3.120 ;
        RECT 1.825 2.610 1.915 3.120 ;
        RECT 2.985 2.610 3.075 3.120 ;
        RECT 4.145 2.610 4.235 3.120 ;
        RECT 0.000 3.120 15.000 3.280 ;
    END
  END vdd
  PIN vss
    DIRECTION INOUT ;
    USE GROUND ;
    SHAPE ABUTMENT ;
    PORT
      LAYER MET1 ;
        RECT 0.000 -0.080 15.000 0.080 ;
        RECT 2.405 0.080 2.495 0.590 ;
        RECT 3.565 0.080 3.655 0.590 ;
        RECT 4.725 0.080 4.815 0.590 ;
        RECT 7.045 0.080 7.135 0.590 ;
        RECT 8.205 0.080 8.295 0.590 ;
        RECT 9.365 0.080 9.455 0.590 ;
        RECT 9.945 0.080 10.035 0.590 ;
        RECT 11.105 0.080 11.195 0.590 ;
        RECT 12.265 0.080 12.355 0.590 ;
        RECT 2.365 0.590 2.535 0.730 ;
        RECT 3.525 0.590 3.695 0.730 ;
        RECT 4.685 0.590 4.855 0.730 ;
        RECT 7.005 0.590 7.175 0.730 ;
        RECT 8.165 0.590 8.335 0.730 ;
        RECT 9.325 0.590 9.495 0.730 ;
        RECT 9.905 0.590 10.075 0.730 ;
        RECT 11.065 0.590 11.235 0.730 ;
        RECT 12.225 0.590 12.395 0.730 ;
    END
  END vss
  PIN zn
    DIRECTION OUTPUT ;
    USE SIGNAL ;
    ANTENNADIFFAREA 2.496000 ;
    PORT
      LAYER MET1 ;
        RECT 2.945 0.840 3.115 0.865 ;
        RECT 4.105 0.840 4.275 0.980 ;
        RECT 7.585 0.840 7.755 0.980 ;
        RECT 8.745 0.840 8.915 0.980 ;
        RECT 10.485 0.840 10.655 0.980 ;
        RECT 11.645 0.840 11.815 0.980 ;
        RECT 2.945 0.865 3.365 0.955 ;
        RECT 2.945 0.955 3.115 0.980 ;
        RECT 3.275 0.955 3.365 1.285 ;
        RECT 4.145 0.980 4.235 1.285 ;
        RECT 7.625 0.980 7.715 1.285 ;
        RECT 8.785 0.980 8.875 1.285 ;
        RECT 10.525 0.980 10.615 1.285 ;
        RECT 11.685 0.980 11.775 1.285 ;
        RECT 3.275 1.285 11.775 1.375 ;
        RECT 10.525 1.375 10.615 2.020 ;
        RECT 11.685 1.375 11.775 1.575 ;
        RECT 11.685 1.575 14.095 1.665 ;
        RECT 11.685 1.665 11.775 2.020 ;
        RECT 12.845 1.665 12.935 2.020 ;
        RECT 14.005 1.665 14.095 2.020 ;
        RECT 10.485 2.020 10.655 2.160 ;
        RECT 11.645 2.020 11.815 2.160 ;
        RECT 12.805 2.020 12.975 2.160 ;
        RECT 13.965 2.020 14.135 2.160 ;
    END
  END zn
  OBS
    LAYER MET1 ;
      RECT 0.375 1.575 9.455 1.665 ;
      RECT 0.375 1.665 0.465 2.045 ;
      RECT 1.245 1.665 1.335 2.020 ;
      RECT 2.405 1.665 2.495 2.020 ;
      RECT 3.565 1.665 3.655 2.020 ;
      RECT 4.725 1.665 4.815 2.020 ;
      RECT 5.885 1.665 5.975 2.020 ;
      RECT 7.045 1.665 7.135 2.020 ;
      RECT 8.205 1.665 8.295 2.020 ;
      RECT 9.365 1.665 9.455 2.020 ;
      RECT 0.045 2.020 0.215 2.045 ;
      RECT 1.205 2.020 1.375 2.160 ;
      RECT 2.365 2.020 2.535 2.160 ;
      RECT 3.525 2.020 3.695 2.160 ;
      RECT 4.685 2.020 4.855 2.160 ;
      RECT 5.845 2.020 6.015 2.160 ;
      RECT 7.005 2.020 7.175 2.160 ;
      RECT 8.165 2.020 8.335 2.160 ;
      RECT 9.325 2.020 9.495 2.160 ;
      RECT 0.045 2.045 0.465 2.135 ;
      RECT 0.045 2.135 0.215 2.160 ;
      RECT 5.265 2.470 5.435 2.495 ;
      RECT 6.425 2.470 6.595 2.495 ;
      RECT 7.585 2.470 7.755 2.495 ;
      RECT 8.745 2.470 8.915 2.495 ;
      RECT 9.905 2.470 10.075 2.495 ;
      RECT 11.065 2.470 11.235 2.495 ;
      RECT 12.225 2.470 12.395 2.495 ;
      RECT 13.385 2.470 13.555 2.495 ;
      RECT 14.545 2.470 14.715 2.495 ;
      RECT 5.265 2.495 5.685 2.585 ;
      RECT 6.175 2.495 6.845 2.585 ;
      RECT 7.335 2.495 8.005 2.585 ;
      RECT 8.495 2.495 9.165 2.585 ;
      RECT 9.655 2.495 10.325 2.585 ;
      RECT 10.815 2.495 11.485 2.585 ;
      RECT 11.975 2.495 12.645 2.585 ;
      RECT 13.135 2.495 13.805 2.585 ;
      RECT 14.295 2.495 14.715 2.585 ;
      RECT 5.265 2.585 5.435 2.610 ;
      RECT 5.595 2.585 5.685 2.915 ;
      RECT 6.175 2.585 6.265 2.915 ;
      RECT 6.425 2.585 6.595 2.610 ;
      RECT 6.755 2.585 6.845 2.915 ;
      RECT 7.335 2.585 7.425 2.915 ;
      RECT 7.585 2.585 7.755 2.610 ;
      RECT 7.915 2.585 8.005 2.915 ;
      RECT 8.495 2.585 8.585 2.915 ;
      RECT 8.745 2.585 8.915 2.610 ;
      RECT 9.075 2.585 9.165 2.915 ;
      RECT 9.655 2.585 9.745 2.915 ;
      RECT 9.905 2.585 10.075 2.610 ;
      RECT 10.235 2.585 10.325 2.915 ;
      RECT 10.815 2.585 10.905 2.915 ;
      RECT 11.065 2.585 11.235 2.610 ;
      RECT 11.395 2.585 11.485 2.915 ;
      RECT 11.975 2.585 12.065 2.915 ;
      RECT 12.225 2.585 12.395 2.610 ;
      RECT 12.555 2.585 12.645 2.915 ;
      RECT 13.135 2.585 13.225 2.915 ;
      RECT 13.385 2.585 13.555 2.610 ;
      RECT 13.715 2.585 13.805 2.915 ;
      RECT 14.295 2.585 14.385 2.915 ;
      RECT 14.545 2.585 14.715 2.610 ;
      RECT 5.595 2.915 6.265 3.005 ;
      RECT 6.755 2.915 7.425 3.005 ;
      RECT 7.915 2.915 8.585 3.005 ;
      RECT 9.075 2.915 9.745 3.005 ;
      RECT 10.235 2.915 10.905 3.005 ;
      RECT 11.395 2.915 12.065 3.005 ;
      RECT 12.555 2.915 13.225 3.005 ;
      RECT 13.715 2.915 14.385 3.005 ;
  END
END ics55f_NR3D4

MACRO ics55f_AN2D1
  CLASS CORE ;
  FOREIGN ics55f_AN2D1 ;
  ORIGIN 0.000 0.000 ;
  SIZE 2.200 BY 3.200 ;
  SYMMETRY X Y R90 ;
  SITE obssite ;
  PIN a1
    DIRECTION INPUT ;
    USE SIGNAL ;
    ANTENNAGATEAREA 0.057900 ;
    PORT
      LAYER POLY ;
        RECT 1.550 0.445 1.610 1.245 ;
        RECT 1.495 1.245 1.665 1.415 ;
        RECT 1.550 1.415 1.610 2.755 ;
      LAYER MET1 ;
        RECT 1.495 1.260 1.665 1.400 ;
        RECT 1.535 1.400 1.625 1.665 ;
    END
  END a1
  PIN a2
    DIRECTION INPUT ;
    USE SIGNAL ;
    ANTENNAGATEAREA 0.057900 ;
    PORT
      LAYER POLY ;
        RECT 0.970 0.445 1.030 1.535 ;
        RECT 0.915 1.535 1.085 1.705 ;
        RECT 0.970 1.705 1.030 2.755 ;
      LAYER MET1 ;
        RECT 0.915 1.550 1.085 1.690 ;
        RECT 0.955 1.690 1.045 2.135 ;
    END
  END a2
  PIN vdd
    DIRECTION INOUT ;
    USE POWER ;
    SHAPE ABUTMENT ;
    PORT
      LAYER MET1 ;
        RECT 0.625 2.470 0.795 2.610 ;
        RECT 1.785 2.470 1.955 2.610 ;
        RECT 0.665 2.610 0.755 3.120 ;
        RECT 1.825 2.610 1.915 3.120 ;
        RECT 0.000 3.120 2.200 3.280 ;
    END
  END vdd
  PIN vss
    DIRECTION INOUT ;
    USE GROUND ;
    SHAPE ABUTMENT ;
    PORT
      LAYER MET1 ;
        RECT 0.000 -0.080 2.200 0.080 ;
        RECT 0.665 0.080 0.755 0.590 ;
        RECT 0.625 0.590 0.795 0.730 ;
    END
  END vss
  PIN z
    DIRECTION OUTPUT ;
    USE SIGNAL ;
    ANTENNADIFFAREA 0.335000 ;
    PORT
      LAYER MET1 ;
        RECT 0.045 0.840 0.215 0.980 ;
        RECT 0.085 0.980 0.175 2.020 ;
        RECT 0.045 2.020 0.215 2.160 ;
    END
  END z
  OBS
    LAYER MET1 ;
      RECT 1.785 0.590 1.955 0.615 ;
      RECT 1.535 0.615 1.955 0.705 ;
      RECT 1.535 0.705 1.625 0.865 ;
      RECT 1.785 0.705 1.955 0.730 ;
      RECT 0.955 0.865 1.625 0.955 ;
      RECT 0.955 0.955 1.045 1.285 ;
      RECT 1.245 0.955 1.335 2.020 ;
      RECT 0.335 1.260 0.505 1.285 ;
      RECT 0.335 1.285 1.045 1.375 ;
      RECT 0.335 1.375 0.505 1.400 ;
      RECT 1.205 2.020 1.375 2.160 ;
  END
END ics55f_AN2D1

MACRO ics55f_AN2D4
  CLASS CORE ;
  FOREIGN ics55f_AN2D4 ;
  ORIGIN 0.000 0.000 ;
  SIZE 5.000 BY 3.200 ;
  SYMMETRY X Y R90 ;
  SITE obssite ;
  PIN a1
    DIRECTION INPUT ;
    USE SIGNAL ;
    ANTENNAGATEAREA 0.120000 ;
    PORT
      LAYER POLY ;
        RECT 3.815 0.155 3.985 0.325 ;
        RECT 3.870 0.325 3.930 1.300 ;
        RECT 3.290 0.445 3.350 1.300 ;
        RECT 3.290 1.300 3.930 1.360 ;
        RECT 3.290 1.360 3.350 2.755 ;
        RECT 3.870 1.360 3.930 2.755 ;
      LAYER MET1 ;
        RECT 3.815 0.170 3.985 0.310 ;
        RECT 3.855 0.310 3.945 0.705 ;
    END
  END a1
  PIN a2
    DIRECTION INPUT ;
    USE SIGNAL ;
    ANTENNAGATEAREA 0.120000 ;
    PORT
      LAYER POLY ;
        RECT 2.710 0.445 2.770 1.245 ;
        RECT 4.450 0.445 4.510 1.300 ;
        RECT 2.655 1.245 2.825 1.415 ;
        RECT 4.105 1.245 4.275 1.300 ;
        RECT 4.105 1.300 4.510 1.360 ;
        RECT 4.105 1.360 4.275 1.415 ;
        RECT 4.450 1.360 4.510 2.755 ;
        RECT 2.710 1.415 2.770 2.755 ;
      LAYER MET1 ;
        RECT 2.655 1.260 2.825 1.285 ;
        RECT 4.105 1.260 4.275 1.285 ;
        RECT 2.655 1.285 4.275 1.375 ;
        RECT 2.655 1.375 2.825 1.400 ;
        RECT 4.105 1.375 4.275 1.400 ;
    END
  END a2
  PIN vdd
    DIRECTION INOUT ;
    USE POWER ;
    SHAPE ABUTMENT ;
    PORT
      LAYER MET1 ;
        RECT 0.045 2.470 0.215 2.610 ;
        RECT 1.205 2.470 1.375 2.610 ;
        RECT 2.365 2.470 2.535 2.610 ;
        RECT 3.525 2.470 3.695 2.610 ;
        RECT 4.685 2.470 4.855 2.610 ;
        RECT 0.085 2.610 0.175 3.120 ;
        RECT 1.245 2.610 1.335 3.120 ;
        RECT 2.405 2.610 2.495 3.120 ;
        RECT 3.565 2.610 3.655 3.120 ;
        RECT 4.725 2.610 4.815 3.120 ;
        RECT 0.000 3.120 5.000 3.280 ;
    END
  END vdd
  PIN vss
    DIRECTION INOUT ;
    USE GROUND ;
    SHAPE ABUTMENT ;
    PORT
      LAYER MET1 ;
        RECT 0.000 -0.080 5.000 0.080 ;
        RECT 0.085 0.080 0.175 0.590 ;
        RECT 1.245 0.080 1.335 0.590 ;
        RECT 2.405 0.080 2.495 0.590 ;
        RECT 4.725 0.080 4.815 0.590 ;
        RECT 0.045 0.590 0.215 0.730 ;
        RECT 1.205 0.590 1.375 0.730 ;
        RECT 2.365 0.590 2.535 0.730 ;
        RECT 4.685 0.590 4.855 0.730 ;
    END
  END vss
  PIN z
    DIRECTION OUTPUT ;
    USE SIGNAL ;
    ANTENNADIFFAREA 1.040000 ;
    PORT
      LAYER MET1 ;
        RECT 0.625 0.840 0.795 0.865 ;
        RECT 1.785 0.840 1.955 0.980 ;
        RECT 0.625 0.865 1.045 0.955 ;
        RECT 0.625 0.955 0.795 0.980 ;
        RECT 0.955 0.955 1.045 1.285 ;
        RECT 0.665 0.980 0.755 2.020 ;
        RECT 1.825 0.980 1.915 1.285 ;
        RECT 0.955 1.285 1.915 1.375 ;
        RECT 1.825 1.375 1.915 2.020 ;
        RECT 0.625 2.020 0.795 2.160 ;
        RECT 1.785 2.020 1.955 2.160 ;
    END
  END z
  OBS
    LAYER MET1 ;
      RECT 2.655 0.170 2.825 0.195 ;
      RECT 2.655 0.195 3.365 0.285 ;
      RECT 2.655 0.285 2.825 0.310 ;
      RECT 3.275 0.285 3.365 0.615 ;
      RECT 3.525 0.590 3.695 0.615 ;
      RECT 3.275 0.615 3.695 0.705 ;
      RECT 3.525 0.705 3.695 0.730 ;
      RECT 2.365 1.550 2.535 1.575 ;
      RECT 2.365 1.575 4.235 1.665 ;
      RECT 2.365 1.665 2.535 1.690 ;
      RECT 2.985 1.665 3.075 2.020 ;
      RECT 4.145 1.665 4.235 2.020 ;
      RECT 2.945 2.020 3.115 2.160 ;
      RECT 4.105 2.020 4.275 2.160 ;
  END
END ics55f_AN2D4

MACRO ics55f_OR2D1
  CLASS CORE ;
  FOREIGN ics55f_OR2D1 ;
  ORIGIN 0.000 0.000 ;
  SIZE 2.200 BY 3.200 ;
  SYMMETRY X Y R90 ;
  SITE obssite ;
  PIN a1
    DIRECTION INPUT ;
    USE SIGNAL ;
    ANTENNAGATEAREA 0.057900 ;
    PORT
      LAYER POLY ;
        RECT 1.550 0.445 1.610 1.535 ;
        RECT 1.495 1.535 1.665 1.705 ;
        RECT 1.550 1.705 1.610 2.755 ;
      LAYER MET1 ;
        RECT 1.495 1.550 1.665 1.690 ;
        RECT 1.535 1.690 1.625 2.135 ;
    END
  END a1
  PIN a2
    DIRECTION INPUT ;
    USE SIGNAL ;
    ANTENNAGATEAREA 0.057900 ;
    PORT
      LAYER POLY ;
        RECT 0.970 0.445 1.030 1.535 ;
        RECT 0.915 1.535 1.085 1.705 ;
        RECT 0.970 1.705 1.030 2.755 ;
      LAYER MET1 ;
        RECT 0.915 1.550 1.085 1.690 ;
        RECT 0.955 1.690 1.045 2.135 ;
    END
  END a2
  PIN vdd
    DIRECTION INOUT ;
    USE POWER ;
    SHAPE ABUTMENT ;
    PORT
      LAYER MET1 ;
        RECT 0.625 2.470 0.795 2.610 ;
        RECT 0.665 2.610 0.755 3.120 ;
        RECT 0.000 3.120 2.200 3.280 ;
    END
  END vdd
  PIN vss
    DIRECTION INOUT ;
    USE GROUND ;
    SHAPE ABUTMENT ;
    PORT
      LAYER MET1 ;
        RECT 0.000 -0.080 2.200 0.080 ;
        RECT 0.665 0.080 0.755 0.590 ;
        RECT 1.825 0.080 1.915 0.590 ;
        RECT 0.625 0.590 0.795 0.730 ;
        RECT 1.785 0.590 1.955 0.730 ;
    END
  END vss
  PIN z
    DIRECTION OUTPUT ;
    USE SIGNAL ;
    ANTENNADIFFAREA 0.323275 ;
    PORT
      LAYER MET1 ;
        RECT 0.045 0.590 0.215 0.730 ;
        RECT 0.085 0.730 0.175 2.020 ;
        RECT 0.045 2.020 0.215 2.160 ;
    END
  END z
  OBS
    LAYER MET1 ;
      RECT 1.205 0.590 1.375 0.730 ;
      RECT 1.245 0.730 1.335 1.285 ;
      RECT 0.625 1.260 0.795 1.285 ;
      RECT 0.625 1.285 1.915 1.375 ;
      RECT 0.625 1.375 0.795 1.400 ;
      RECT 1.825 1.375 1.915 2.020 ;
      RECT 1.785 2.020 1.955 2.160 ;
  END
END ics55f_OR2D1

MACRO ics55f_AO21D1
  CLASS CORE ;
  FOREIGN ics55f_AO21D1 ;
  ORIGIN 0.000 0.000 ;
  SIZE 2.800 BY 3.200 ;
  SYMMETRY X Y R90 ;
  SITE obssite ;
  PIN a1
    DIRECTION INPUT ;
    USE SIGNAL ;
    ANTENNAGATEAREA 0.060000 ;
    PORT
      LAYER POLY ;
        RECT 0.970 0.445 1.030 1.535 ;
        RECT 0.915 1.535 1.085 1.705 ;
        RECT 0.970 1.705 1.030 2.755 ;
      LAYER MET1 ;
        RECT 0.915 1.550 1.085 1.690 ;
        RECT 0.955 1.690 1.045 2.135 ;
    END
  END a1
  PIN a2
    DIRECTION INPUT ;
    USE SIGNAL ;
    ANTENNAGATEAREA 0.060000 ;
    PORT
      LAYER POLY ;
        RECT 0.390 0.445 0.450 1.245 ;
        RECT 0.335 1.245 0.505 1.415 ;
        RECT 0.390 1.415 0.450 2.755 ;
      LAYER MET1 ;
        RECT 0.335 1.260 0.505 1.400 ;
        RECT 0.375 1.400 0.465 1.665 ;
    END
  END a2
  PIN b
    DIRECTION INPUT ;
    USE SIGNAL ;
    ANTENNAGATEAREA 0.060000 ;
    PORT
      LAYER POLY ;
        RECT 1.550 0.445 1.610 1.535 ;
        RECT 1.495 1.535 1.665 1.705 ;
        RECT 1.550 1.705 1.610 2.755 ;
      LAYER MET1 ;
        RECT 1.495 1.550 1.665 1.690 ;
        RECT 1.535 1.690 1.625 2.135 ;
    END
  END b
  PIN vdd
    DIRECTION INOUT ;
    USE POWER ;
    SHAPE ABUTMENT ;
    PORT
      LAYER MET1 ;
        RECT 1.785 2.470 1.955 2.610 ;
        RECT 1.825 2.610 1.915 3.120 ;
        RECT 0.000 3.120 2.800 3.280 ;
    END
  END vdd
  PIN vss
    DIRECTION INOUT ;
    USE GROUND ;
    SHAPE ABUTMENT ;
    PORT
      LAYER MET1 ;
        RECT 0.000 -0.080 2.800 0.080 ;
        RECT 0.085 0.080 0.175 0.590 ;
        RECT 1.825 0.080 1.915 0.590 ;
        RECT 0.045 0.590 0.215 0.730 ;
        RECT 1.785 0.590 1.955 0.730 ;
    END
  END vss
  PIN z
    DIRECTION OUTPUT ;
    USE SIGNAL ;
    ANTENNADIFFAREA 0.335000 ;
    PORT
      LAYER MET1 ;
        RECT 2.365 0.840 2.535 0.980 ;
        RECT 2.405 0.980 2.495 2.020 ;
        RECT 2.365 2.020 2.535 2.160 ;
    END
  END z
  OBS
    LAYER MET1 ;
      RECT 1.205 0.840 1.375 0.980 ;
      RECT 1.245 0.980 1.335 1.285 ;
      RECT 2.075 1.260 2.245 1.285 ;
      RECT 0.665 1.285 2.245 1.375 ;
      RECT 0.665 1.375 0.755 2.020 ;
      RECT 2.075 1.375 2.245 1.400 ;
      RECT 0.625 2.020 0.795 2.160 ;
      RECT 0.045 2.470 0.215 2.495 ;
      RECT 1.205 2.470 1.375 2.495 ;
      RECT 0.045 2.495 0.465 2.585 ;
      RECT 0.955 2.495 1.375 2.585 ;
      RECT 0.045 2.585 0.215 2.610 ;
      RECT 0.375 2.585 0.465 2.915 ;
      RECT 0.955 2.585 1.045 2.915 ;
      RECT 1.205 2.585 1.375 2.610 ;
      RECT 0.375 2.915 1.045 3.005 ;
  END
END ics55f_AO21D1

MACRO ics55f_OA21D1
  CLASS CORE ;
  FOREIGN ics55f_OA21D1 ;
  ORIGIN 0.000 0.000 ;
  SIZE 2.800 BY 3.200 ;
  SYMMETRY X Y R90 ;
  SITE obssite ;
  PIN a1
    DIRECTION INPUT ;
    USE SIGNAL ;
    ANTENNAGATEAREA 0.060000 ;
    PORT
      LAYER POLY ;
        RECT 1.550 0.445 1.610 1.535 ;
        RECT 1.495 1.535 1.665 1.705 ;
        RECT 1.550 1.705 1.610 2.755 ;
      LAYER MET1 ;
        RECT 1.495 1.550 1.665 1.690 ;
        RECT 1.535 1.690 1.625 2.135 ;
    END
  END a1
  PIN a2
    DIRECTION INPUT ;
    USE SIGNAL ;
    ANTENNAGATEAREA 0.060000 ;
    PORT
      LAYER POLY ;
        RECT 2.130 0.445 2.190 1.245 ;
        RECT 2.075 1.245 2.245 1.415 ;
        RECT 2.130 1.415 2.190 2.755 ;
      LAYER MET1 ;
        RECT 2.075 1.260 2.245 1.400 ;
        RECT 2.115 1.400 2.205 1.665 ;
    END
  END a2
  PIN b
    DIRECTION INPUT ;
    USE SIGNAL ;
    ANTENNAGATEAREA 0.060000 ;
    PORT
      LAYER POLY ;
        RECT 0.970 0.445 1.030 1.535 ;
        RECT 0.915 1.535 1.085 1.705 ;
        RECT 0.970 1.705 1.030 2.755 ;
      LAYER MET1 ;
        RECT 0.915 1.550 1.085 1.690 ;
        RECT 0.955 1.690 1.045 2.135 ;
    END
  END b
  PIN vdd
    DIRECTION INOUT ;
    USE POWER ;
    SHAPE ABUTMENT ;
    PORT
      LAYER MET1 ;
        RECT 0.625 2.470 0.795 2.610 ;
        RECT 2.365 2.470 2.535 2.610 ;
        RECT 0.665 2.610 0.755 3.120 ;
        RECT 2.405 2.610 2.495 3.120 ;
        RECT 0.000 3.120 2.800 3.280 ;
    END
  END vdd
  PIN vss
    DIRECTION INOUT ;
    USE GROUND ;
    SHAPE ABUTMENT ;
    PORT
      LAYER MET1 ;
        RECT 0.000 -0.080 2.800 0.080 ;
        RECT 0.665 0.080 0.755 0.590 ;
        RECT 0.625 0.590 0.795 0.730 ;
    END
  END vss
  PIN z
    DIRECTION OUTPUT ;
    USE SIGNAL ;
    ANTENNADIFFAREA 0.335000 ;
    PORT
      LAYER MET1 ;
        RECT 0.045 0.840 0.215 0.980 ;
        RECT 0.085 0.980 0.175 2.020 ;
        RECT 0.045 2.020 0.215 2.160 ;
    END
  END z
  OBS
    LAYER MET1 ;
      RECT 1.535 0.195 2.205 0.285 ;
      RECT 1.535 0.285 1.625 0.615 ;
      RECT 2.115 0.285 2.205 0.615 ;
      RECT 1.205 0.590 1.375 0.615 ;
      RECT 2.365 0.590 2.535 0.615 ;
      RECT 1.205 0.615 1.625 0.705 ;
      RECT 2.115 0.615 2.535 0.705 ;
      RECT 1.205 0.705 1.375 0.730 ;
      RECT 2.365 0.705 2.535 0.730 ;
      RECT 1.785 0.840 1.955 0.865 ;
      RECT 1.535 0.865 1.955 0.955 ;
      RECT 1.535 0.955 1.625 1.285 ;
      RECT 1.785 0.955 1.955 0.980 ;
      RECT 0.335 1.260 0.505 1.285 ;
      RECT 0.335 1.285 1.625 1.375 ;
      RECT 0.335 1.375 0.505 1.400 ;
      RECT 1.245 1.375 1.335 2.020 ;
      RECT 1.205 2.020 1.375 2.160 ;
  END
END ics55f_OA21D1

MACRO ics55f_AOI21D1
  CLASS CORE ;
  FOREIGN ics55f_AOI21D1 ;
  ORIGIN 0.000 0.000 ;
  SIZE 2.200 BY 3.200 ;
  SYMMETRY X Y R90 ;
  SITE obssite ;
  PIN a1
    DIRECTION INPUT ;
    USE SIGNAL ;
    ANTENNAGATEAREA 0.060000 ;
    PORT
      LAYER POLY ;
        RECT 0.970 0.445 1.030 1.245 ;
        RECT 0.915 1.245 1.085 1.415 ;
        RECT 0.970 1.415 1.030 2.755 ;
      LAYER MET1 ;
        RECT 0.955 0.865 1.045 1.260 ;
        RECT 0.915 1.260 1.085 1.400 ;
    END
  END a1
  PIN a2
    DIRECTION INPUT ;
    USE SIGNAL ;
    ANTENNAGATEAREA 0.060000 ;
    PORT
      LAYER POLY ;
        RECT 1.550 0.445 1.610 1.245 ;
        RECT 1.495 1.245 1.665 1.415 ;
        RECT 1.550 1.415 1.610 2.755 ;
      LAYER MET1 ;
        RECT 1.495 1.260 1.665 1.400 ;
        RECT 1.535 1.400 1.625 1.665 ;
    END
  END a2
  PIN b
    DIRECTION INPUT ;
    USE SIGNAL ;
    ANTENNAGATEAREA 0.060000 ;
    PORT
      LAYER POLY ;
        RECT 0.390 0.445 0.450 1.245 ;
        RECT 0.335 1.245 0.505 1.415 ;
        RECT 0.390 1.415 0.450 2.755 ;
      LAYER MET1 ;
        RECT 0.335 1.260 0.505 1.400 ;
        RECT 0.375 1.400 0.465 1.665 ;
    END
  END b
  PIN vdd
    DIRECTION INOUT ;
    USE POWER ;
    SHAPE ABUTMENT ;
    PORT
      LAYER MET1 ;
        RECT 0.045 2.470 0.215 2.610 ;
        RECT 0.085 2.610 0.175 3.120 ;
        RECT 0.000 3.120 2.200 3.280 ;
    END
  END vdd
  PIN vss
    DIRECTION INOUT ;
    USE GROUND ;
    SHAPE ABUTMENT ;
    PORT
      LAYER MET1 ;
        RECT 0.000 -0.080 2.200 0.080 ;
        RECT 0.085 0.080 0.175 0.590 ;
        RECT 1.825 0.080 1.915 0.590 ;
        RECT 0.045 0.590 0.215 0.730 ;
        RECT 1.785 0.590 1.955 0.730 ;
    END
  END vss
  PIN zn
    DIRECTION OUTPUT ;
    USE SIGNAL ;
    ANTENNADIFFAREA 0.520000 ;
    PORT
      LAYER MET1 ;
        RECT 0.625 0.840 0.795 0.980 ;
        RECT 0.665 0.980 0.755 1.575 ;
        RECT 0.665 1.575 1.335 1.665 ;
        RECT 1.245 1.665 1.335 2.020 ;
        RECT 1.205 2.020 1.375 2.160 ;
    END
  END zn
  OBS
    LAYER MET1 ;
      RECT 0.625 2.470 0.795 2.495 ;
      RECT 1.785 2.470 1.955 2.495 ;
      RECT 0.625 2.495 1.045 2.585 ;
      RECT 1.535 2.495 1.955 2.585 ;
      RECT 0.625 2.585 0.795 2.610 ;
      RECT 0.955 2.585 1.045 2.915 ;
      RECT 1.535 2.585 1.625 2.915 ;
      RECT 1.785 2.585 1.955 2.610 ;
      RECT 0.955 2.915 1.625 3.005 ;
  END
END ics55f_AOI21D1

MACRO ics55f_OAI21D1
  CLASS CORE ;
  FOREIGN ics55f_OAI21D1 ;
  ORIGIN 0.000 0.000 ;
  SIZE 2.200 BY 3.200 ;
  SYMMETRY X Y R90 ;
  SITE obssite ;
  PIN a1
    DIRECTION INPUT ;
    USE SIGNAL ;
    ANTENNAGATEAREA 0.060000 ;
    PORT
      LAYER POLY ;
        RECT 0.970 0.445 1.030 1.245 ;
        RECT 0.915 1.245 1.085 1.415 ;
        RECT 0.970 1.415 1.030 2.755 ;
      LAYER MET1 ;
        RECT 0.955 0.865 1.045 1.260 ;
        RECT 0.915 1.260 1.085 1.400 ;
    END
  END a1
  PIN a2
    DIRECTION INPUT ;
    USE SIGNAL ;
    ANTENNAGATEAREA 0.060000 ;
    PORT
      LAYER POLY ;
        RECT 0.390 0.445 0.450 1.245 ;
        RECT 0.335 1.245 0.505 1.415 ;
        RECT 0.390 1.415 0.450 2.755 ;
      LAYER MET1 ;
        RECT 0.335 1.260 0.505 1.400 ;
        RECT 0.375 1.400 0.465 1.665 ;
    END
  END a2
  PIN b
    DIRECTION INPUT ;
    USE SIGNAL ;
    ANTENNAGATEAREA 0.060000 ;
    PORT
      LAYER POLY ;
        RECT 1.550 0.445 1.610 1.245 ;
        RECT 1.495 1.245 1.665 1.415 ;
        RECT 1.550 1.415 1.610 2.755 ;
      LAYER MET1 ;
        RECT 1.495 1.260 1.665 1.400 ;
        RECT 1.535 1.400 1.625 1.665 ;
    END
  END b
  PIN vdd
    DIRECTION INOUT ;
    USE POWER ;
    SHAPE ABUTMENT ;
    PORT
      LAYER MET1 ;
        RECT 0.045 2.470 0.215 2.610 ;
        RECT 1.785 2.470 1.955 2.610 ;
        RECT 0.085 2.610 0.175 3.120 ;
        RECT 1.825 2.610 1.915 3.120 ;
        RECT 0.000 3.120 2.200 3.280 ;
    END
  END vdd
  PIN vss
    DIRECTION INOUT ;
    USE GROUND ;
    SHAPE ABUTMENT ;
    PORT
      LAYER MET1 ;
        RECT 0.000 -0.080 2.200 0.080 ;
        RECT 1.825 0.080 1.915 0.590 ;
        RECT 1.785 0.590 1.955 0.730 ;
    END
  END vss
  PIN zn
    DIRECTION OUTPUT ;
    USE SIGNAL ;
    ANTENNADIFFAREA 0.520000 ;
    PORT
      LAYER MET1 ;
        RECT 0.625 0.840 0.795 0.980 ;
        RECT 0.665 0.980 0.755 1.575 ;
        RECT 0.665 1.575 1.335 1.665 ;
        RECT 1.245 1.665 1.335 2.020 ;
        RECT 1.205 2.020 1.375 2.160 ;
    END
  END zn
  OBS
    LAYER MET1 ;
      RECT 0.375 0.195 1.045 0.285 ;
      RECT 0.375 0.285 0.465 0.615 ;
      RECT 0.955 0.285 1.045 0.615 ;
      RECT 0.045 0.590 0.215 0.615 ;
      RECT 1.205 0.590 1.375 0.615 ;
      RECT 0.045 0.615 0.465 0.705 ;
      RECT 0.955 0.615 1.375 0.705 ;
      RECT 0.045 0.705 0.215 0.730 ;
      RECT 1.205 0.705 1.375 0.730 ;
  END
END ics55f_OAI21D1

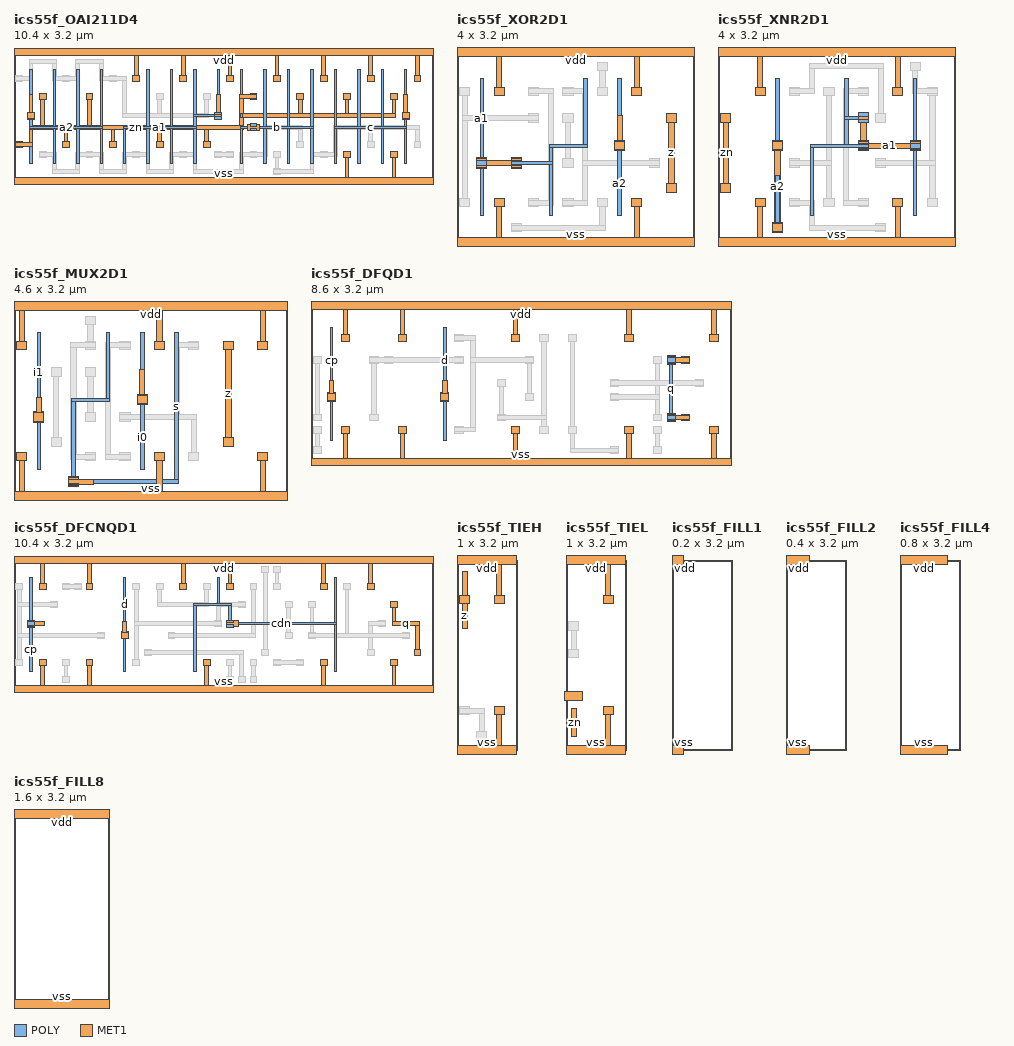
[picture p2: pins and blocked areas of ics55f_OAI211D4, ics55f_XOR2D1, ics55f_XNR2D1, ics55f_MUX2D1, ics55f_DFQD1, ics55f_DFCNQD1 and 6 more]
MACRO ics55f_OAI211D4
  CLASS CORE ;
  FOREIGN ics55f_OAI211D4 ;
  ORIGIN 0.000 0.000 ;
  SIZE 10.400 BY 3.200 ;
  SYMMETRY X Y R90 ;
  SITE obssite ;
  PIN a1
    DIRECTION INPUT ;
    USE SIGNAL ;
    ANTENNAGATEAREA 0.240000 ;
    PORT
      LAYER POLY ;
        RECT 2.710 0.445 2.770 1.300 ;
        RECT 3.290 0.445 3.350 1.300 ;
        RECT 3.870 0.445 3.930 1.300 ;
        RECT 4.450 0.445 4.510 1.300 ;
        RECT 2.710 1.300 4.510 1.360 ;
        RECT 3.290 1.360 3.350 2.755 ;
        RECT 3.870 1.360 3.930 2.755 ;
        RECT 4.450 1.360 4.510 1.590 ;
        RECT 4.975 1.535 5.145 1.590 ;
        RECT 4.450 1.590 5.145 1.650 ;
        RECT 4.450 1.650 4.510 2.755 ;
        RECT 4.975 1.650 5.145 1.705 ;
        RECT 5.030 1.705 5.090 2.755 ;
      LAYER MET1 ;
        RECT 4.975 1.550 5.145 1.690 ;
        RECT 5.015 1.690 5.105 2.135 ;
    END
  END a1
  PIN a2
    DIRECTION INPUT ;
    USE SIGNAL ;
    ANTENNAGATEAREA 0.240000 ;
    PORT
      LAYER POLY ;
        RECT 0.390 0.445 0.450 1.300 ;
        RECT 0.970 0.445 1.030 1.300 ;
        RECT 1.550 0.445 1.610 1.300 ;
        RECT 2.130 0.445 2.190 1.300 ;
        RECT 0.390 1.300 2.190 1.360 ;
        RECT 0.390 1.360 0.450 1.535 ;
        RECT 0.970 1.360 1.030 2.755 ;
        RECT 1.550 1.360 1.610 2.755 ;
        RECT 2.130 1.360 2.190 2.755 ;
        RECT 0.335 1.535 0.505 1.705 ;
        RECT 0.390 1.705 0.450 2.755 ;
      LAYER MET1 ;
        RECT 0.335 1.550 0.505 1.690 ;
        RECT 0.375 1.690 0.465 2.135 ;
    END
  END a2
  PIN b
    DIRECTION INPUT ;
    USE SIGNAL ;
    ANTENNAGATEAREA 0.240000 ;
    PORT
      LAYER POLY ;
        RECT 5.610 0.445 5.670 1.300 ;
        RECT 6.190 0.445 6.250 1.300 ;
        RECT 6.770 0.445 6.830 1.300 ;
        RECT 7.350 0.445 7.410 1.300 ;
        RECT 5.845 1.245 6.015 1.300 ;
        RECT 5.610 1.300 7.410 1.360 ;
        RECT 5.610 1.360 5.670 2.755 ;
        RECT 5.845 1.360 6.015 1.415 ;
        RECT 6.190 1.360 6.250 2.755 ;
        RECT 6.770 1.360 6.830 2.755 ;
        RECT 7.350 1.360 7.410 2.755 ;
      LAYER MET1 ;
        RECT 5.780 1.260 6.080 1.400 ;
    END
  END b
  PIN c
    DIRECTION INPUT ;
    USE SIGNAL ;
    ANTENNAGATEAREA 0.240000 ;
    PORT
      LAYER POLY ;
        RECT 7.930 0.445 7.990 1.300 ;
        RECT 8.510 0.445 8.570 1.300 ;
        RECT 9.090 0.445 9.150 1.300 ;
        RECT 9.670 0.445 9.730 1.300 ;
        RECT 7.930 1.300 9.730 1.360 ;
        RECT 7.930 1.360 7.990 2.755 ;
        RECT 8.510 1.360 8.570 2.755 ;
        RECT 9.090 1.360 9.150 2.755 ;
        RECT 9.670 1.360 9.730 1.535 ;
        RECT 9.615 1.535 9.785 1.705 ;
        RECT 9.670 1.705 9.730 2.755 ;
      LAYER MET1 ;
        RECT 9.615 1.550 9.785 1.690 ;
        RECT 9.655 1.690 9.745 2.135 ;
    END
  END c
  PIN vdd
    DIRECTION INOUT ;
    USE POWER ;
    SHAPE ABUTMENT ;
    PORT
      LAYER MET1 ;
        RECT 2.945 2.470 3.115 2.610 ;
        RECT 4.105 2.470 4.275 2.610 ;
        RECT 5.265 2.470 5.435 2.610 ;
        RECT 6.425 2.470 6.595 2.610 ;
        RECT 7.585 2.470 7.755 2.610 ;
        RECT 8.745 2.470 8.915 2.610 ;
        RECT 9.905 2.470 10.075 2.610 ;
        RECT 2.985 2.610 3.075 3.120 ;
        RECT 4.145 2.610 4.235 3.120 ;
        RECT 5.305 2.610 5.395 3.120 ;
        RECT 6.465 2.610 6.555 3.120 ;
        RECT 7.625 2.610 7.715 3.120 ;
        RECT 8.785 2.610 8.875 3.120 ;
        RECT 9.945 2.610 10.035 3.120 ;
        RECT 0.000 3.120 10.400 3.280 ;
    END
  END vdd
  PIN vss
    DIRECTION INOUT ;
    USE GROUND ;
    SHAPE ABUTMENT ;
    PORT
      LAYER MET1 ;
        RECT 0.000 -0.080 10.400 0.080 ;
        RECT 8.205 0.080 8.295 0.590 ;
        RECT 9.365 0.080 9.455 0.590 ;
        RECT 8.165 0.590 8.335 0.730 ;
        RECT 9.325 0.590 9.495 0.730 ;
    END
  END vss
  PIN zn
    DIRECTION OUTPUT ;
    USE SIGNAL ;
    ANTENNADIFFAREA 2.764000 ;
    PORT
      LAYER MET1 ;
        RECT 0.045 0.840 0.215 0.865 ;
        RECT 1.205 0.840 1.375 0.980 ;
        RECT 2.365 0.840 2.535 0.980 ;
        RECT 3.525 0.840 3.695 0.980 ;
        RECT 4.685 0.840 4.855 0.980 ;
        RECT 0.045 0.865 0.465 0.955 ;
        RECT 0.045 0.955 0.215 0.980 ;
        RECT 0.375 0.955 0.465 1.285 ;
        RECT 1.245 0.980 1.335 1.285 ;
        RECT 2.405 0.980 2.495 1.285 ;
        RECT 3.565 0.980 3.655 1.285 ;
        RECT 4.725 0.980 4.815 1.285 ;
        RECT 0.375 1.285 5.685 1.375 ;
        RECT 0.665 1.375 0.755 2.020 ;
        RECT 1.825 1.375 1.915 2.020 ;
        RECT 5.595 1.375 5.685 1.575 ;
        RECT 5.595 1.575 9.455 1.665 ;
        RECT 5.595 1.665 5.685 2.045 ;
        RECT 7.045 1.665 7.135 2.020 ;
        RECT 8.205 1.665 8.295 2.020 ;
        RECT 9.365 1.665 9.455 2.020 ;
        RECT 0.625 2.020 0.795 2.160 ;
        RECT 1.785 2.020 1.955 2.160 ;
        RECT 5.845 2.020 6.015 2.045 ;
        RECT 7.005 2.020 7.175 2.160 ;
        RECT 8.165 2.020 8.335 2.160 ;
        RECT 9.325 2.020 9.495 2.160 ;
        RECT 5.595 2.045 6.015 2.135 ;
        RECT 5.845 2.135 6.015 2.160 ;
    END
  END zn
  OBS
    LAYER MET1 ;
      RECT 6.425 0.170 6.595 0.195 ;
      RECT 0.955 0.195 1.625 0.285 ;
      RECT 2.115 0.195 2.785 0.285 ;
      RECT 3.275 0.195 3.945 0.285 ;
      RECT 4.435 0.195 5.685 0.285 ;
      RECT 6.425 0.195 7.425 0.285 ;
      RECT 0.955 0.285 1.045 0.615 ;
      RECT 1.535 0.285 1.625 0.615 ;
      RECT 2.115 0.285 2.205 0.615 ;
      RECT 2.695 0.285 2.785 0.615 ;
      RECT 3.275 0.285 3.365 0.615 ;
      RECT 3.855 0.285 3.945 0.615 ;
      RECT 4.435 0.285 4.525 0.615 ;
      RECT 5.595 0.285 5.685 0.615 ;
      RECT 6.425 0.285 6.595 0.310 ;
      RECT 7.335 0.285 7.425 0.615 ;
      RECT 6.465 0.310 6.555 0.590 ;
      RECT 0.625 0.590 0.795 0.615 ;
      RECT 1.785 0.590 1.955 0.615 ;
      RECT 2.945 0.590 3.115 0.615 ;
      RECT 4.105 0.590 4.275 0.615 ;
      RECT 4.975 0.590 5.145 0.615 ;
      RECT 5.265 0.590 5.435 0.615 ;
      RECT 5.845 0.590 6.015 0.615 ;
      RECT 6.425 0.590 6.595 0.730 ;
      RECT 7.585 0.590 7.755 0.615 ;
      RECT 0.625 0.615 1.045 0.705 ;
      RECT 1.535 0.615 2.205 0.705 ;
      RECT 2.695 0.615 3.365 0.705 ;
      RECT 3.855 0.615 4.525 0.705 ;
      RECT 4.975 0.615 5.435 0.705 ;
      RECT 5.595 0.615 6.265 0.705 ;
      RECT 7.335 0.615 8.005 0.705 ;
      RECT 0.625 0.705 0.795 0.730 ;
      RECT 1.785 0.705 1.955 0.730 ;
      RECT 2.945 0.705 3.115 0.730 ;
      RECT 4.105 0.705 4.275 0.730 ;
      RECT 4.975 0.705 5.145 0.730 ;
      RECT 5.265 0.705 5.435 0.730 ;
      RECT 5.845 0.705 6.015 0.730 ;
      RECT 6.175 0.705 6.265 1.285 ;
      RECT 7.585 0.705 7.755 0.730 ;
      RECT 7.915 0.705 8.005 1.285 ;
      RECT 7.005 0.840 7.175 0.980 ;
      RECT 8.745 0.840 8.915 0.980 ;
      RECT 9.905 0.840 10.075 0.980 ;
      RECT 7.045 0.980 7.135 1.285 ;
      RECT 8.785 0.980 8.875 1.285 ;
      RECT 9.945 0.980 10.035 1.285 ;
      RECT 6.175 1.285 7.135 1.375 ;
      RECT 7.915 1.285 10.035 1.375 ;
      RECT 2.695 1.575 4.815 1.665 ;
      RECT 2.695 1.665 2.785 2.495 ;
      RECT 3.565 1.665 3.655 2.020 ;
      RECT 4.725 1.665 4.815 2.020 ;
      RECT 3.525 2.020 3.695 2.160 ;
      RECT 4.685 2.020 4.855 2.160 ;
      RECT 0.045 2.470 0.215 2.495 ;
      RECT 1.205 2.470 1.375 2.495 ;
      RECT 2.365 2.470 2.535 2.495 ;
      RECT 0.045 2.495 0.465 2.585 ;
      RECT 0.955 2.495 1.625 2.585 ;
      RECT 2.115 2.495 2.785 2.585 ;
      RECT 0.045 2.585 0.215 2.610 ;
      RECT 0.375 2.585 0.465 2.915 ;
      RECT 0.955 2.585 1.045 2.915 ;
      RECT 1.205 2.585 1.375 2.610 ;
      RECT 1.535 2.585 1.625 2.915 ;
      RECT 2.115 2.585 2.205 2.915 ;
      RECT 2.365 2.585 2.535 2.610 ;
      RECT 0.375 2.915 1.045 3.005 ;
      RECT 1.535 2.915 2.205 3.005 ;
  END
END ics55f_OAI211D4

MACRO ics55f_XOR2D1
  CLASS CORE ;
  FOREIGN ics55f_XOR2D1 ;
  ORIGIN 0.000 0.000 ;
  SIZE 4.000 BY 3.200 ;
  SYMMETRY X Y R90 ;
  SITE obssite ;
  PIN a1
    DIRECTION INPUT ;
    USE SIGNAL ;
    ANTENNAGATEAREA 0.060000 ;
    PORT
      LAYER POLY ;
        RECT 0.390 0.445 0.450 1.245 ;
        RECT 1.550 0.445 1.610 1.300 ;
        RECT 0.335 1.245 0.505 1.415 ;
        RECT 0.915 1.245 1.085 1.300 ;
        RECT 0.915 1.300 1.610 1.360 ;
        RECT 0.915 1.360 1.085 1.415 ;
        RECT 1.550 1.360 1.610 1.590 ;
        RECT 0.390 1.415 0.450 2.755 ;
        RECT 1.550 1.590 2.190 1.650 ;
        RECT 2.130 1.650 2.190 2.755 ;
      LAYER MET1 ;
        RECT 0.335 1.260 0.505 1.285 ;
        RECT 0.915 1.260 1.085 1.285 ;
        RECT 0.335 1.285 1.085 1.375 ;
        RECT 0.335 1.375 0.505 1.400 ;
        RECT 0.915 1.375 1.085 1.400 ;
    END
  END a1
  PIN a2
    DIRECTION INPUT ;
    USE SIGNAL ;
    ANTENNAGATEAREA 0.060000 ;
    PORT
      LAYER POLY ;
        RECT 2.710 0.445 2.770 1.535 ;
        RECT 2.655 1.535 2.825 1.705 ;
        RECT 2.710 1.705 2.770 2.755 ;
      LAYER MET1 ;
        RECT 2.655 1.550 2.825 1.690 ;
        RECT 2.695 1.690 2.785 2.135 ;
    END
  END a2
  PIN vdd
    DIRECTION INOUT ;
    USE POWER ;
    SHAPE ABUTMENT ;
    PORT
      LAYER MET1 ;
        RECT 0.625 2.470 0.795 2.610 ;
        RECT 2.945 2.470 3.115 2.610 ;
        RECT 0.665 2.610 0.755 3.120 ;
        RECT 2.985 2.610 3.075 3.120 ;
        RECT 0.000 3.120 4.000 3.280 ;
    END
  END vdd
  PIN vss
    DIRECTION INOUT ;
    USE GROUND ;
    SHAPE ABUTMENT ;
    PORT
      LAYER MET1 ;
        RECT 0.000 -0.080 4.000 0.080 ;
        RECT 0.665 0.080 0.755 0.590 ;
        RECT 2.985 0.080 3.075 0.590 ;
        RECT 0.625 0.590 0.795 0.730 ;
        RECT 2.945 0.590 3.115 0.730 ;
    END
  END vss
  PIN z
    DIRECTION OUTPUT ;
    USE SIGNAL ;
    ANTENNADIFFAREA 0.335000 ;
    PORT
      LAYER MET1 ;
        RECT 3.525 0.840 3.695 0.980 ;
        RECT 3.565 0.980 3.655 2.020 ;
        RECT 3.525 2.020 3.695 2.160 ;
    END
  END z
  OBS
    LAYER MET1 ;
      RECT 0.915 0.170 1.085 0.195 ;
      RECT 0.915 0.195 2.495 0.285 ;
      RECT 0.915 0.285 1.085 0.310 ;
      RECT 2.405 0.285 2.495 0.590 ;
      RECT 0.045 0.590 0.215 0.730 ;
      RECT 1.205 0.590 1.375 0.615 ;
      RECT 1.785 0.590 1.955 0.615 ;
      RECT 2.365 0.590 2.535 0.730 ;
      RECT 1.205 0.615 1.625 0.705 ;
      RECT 1.785 0.615 2.205 0.705 ;
      RECT 1.205 0.705 1.375 0.730 ;
      RECT 1.535 0.705 1.625 2.495 ;
      RECT 1.785 0.705 1.955 0.730 ;
      RECT 2.115 0.705 2.205 1.285 ;
      RECT 0.085 0.730 0.175 2.045 ;
      RECT 1.785 1.260 1.955 1.400 ;
      RECT 3.235 1.260 3.405 1.285 ;
      RECT 2.115 1.285 3.405 1.375 ;
      RECT 2.115 1.375 2.205 2.495 ;
      RECT 3.235 1.375 3.405 1.400 ;
      RECT 1.825 1.400 1.915 2.020 ;
      RECT 1.205 2.020 1.375 2.045 ;
      RECT 1.785 2.020 1.955 2.160 ;
      RECT 0.085 2.045 1.375 2.135 ;
      RECT 0.085 2.135 0.175 2.470 ;
      RECT 1.205 2.135 1.375 2.160 ;
      RECT 0.045 2.470 0.215 2.610 ;
      RECT 1.205 2.470 1.375 2.495 ;
      RECT 1.785 2.470 1.955 2.495 ;
      RECT 2.365 2.470 2.535 2.610 ;
      RECT 1.205 2.495 1.625 2.585 ;
      RECT 1.785 2.495 2.205 2.585 ;
      RECT 1.205 2.585 1.375 2.610 ;
      RECT 1.785 2.585 1.955 2.610 ;
      RECT 2.405 2.610 2.495 2.890 ;
      RECT 2.365 2.890 2.535 3.030 ;
  END
END ics55f_XOR2D1

MACRO ics55f_XNR2D1
  CLASS CORE ;
  FOREIGN ics55f_XNR2D1 ;
  ORIGIN 0.000 0.000 ;
  SIZE 4.000 BY 3.200 ;
  SYMMETRY X Y R90 ;
  SITE obssite ;
  PIN a1
    DIRECTION INPUT ;
    USE SIGNAL ;
    ANTENNAGATEAREA 0.060000 ;
    PORT
      LAYER POLY ;
        RECT 1.550 0.445 1.610 1.590 ;
        RECT 3.290 0.445 3.350 1.535 ;
        RECT 2.365 1.535 2.535 1.590 ;
        RECT 3.235 1.535 3.405 1.705 ;
        RECT 1.550 1.590 2.535 1.650 ;
        RECT 2.130 1.650 2.190 2.060 ;
        RECT 2.365 1.650 2.535 1.705 ;
        RECT 3.290 1.705 3.350 2.755 ;
        RECT 2.365 2.005 2.535 2.060 ;
        RECT 2.130 2.060 2.535 2.120 ;
        RECT 2.130 2.120 2.190 2.755 ;
        RECT 2.365 2.120 2.535 2.175 ;
      LAYER MET1 ;
        RECT 2.365 1.550 2.535 1.575 ;
        RECT 3.235 1.550 3.405 1.575 ;
        RECT 2.365 1.575 3.405 1.665 ;
        RECT 2.365 1.665 2.535 1.690 ;
        RECT 3.235 1.665 3.405 1.690 ;
        RECT 2.405 1.690 2.495 2.020 ;
        RECT 2.365 2.020 2.535 2.160 ;
    END
  END a1
  PIN a2
    DIRECTION INPUT ;
    USE SIGNAL ;
    ANTENNAGATEAREA 0.060000 ;
    PORT
      LAYER POLY ;
        RECT 0.915 0.155 1.085 0.325 ;
        RECT 0.970 0.325 1.030 1.125 ;
        RECT 0.915 1.535 1.085 1.705 ;
        RECT 0.970 1.705 1.030 2.755 ;
      LAYER MET1 ;
        RECT 0.915 0.170 1.085 0.310 ;
        RECT 0.955 0.310 1.045 1.550 ;
        RECT 0.915 1.550 1.085 1.690 ;
    END
  END a2
  PIN vdd
    DIRECTION INOUT ;
    USE POWER ;
    SHAPE ABUTMENT ;
    PORT
      LAYER MET1 ;
        RECT 0.625 2.470 0.795 2.610 ;
        RECT 2.945 2.470 3.115 2.610 ;
        RECT 0.665 2.610 0.755 3.120 ;
        RECT 2.985 2.610 3.075 3.120 ;
        RECT 0.000 3.120 4.000 3.280 ;
    END
  END vdd
  PIN vss
    DIRECTION INOUT ;
    USE GROUND ;
    SHAPE ABUTMENT ;
    PORT
      LAYER MET1 ;
        RECT 0.000 -0.080 4.000 0.080 ;
        RECT 0.665 0.080 0.755 0.590 ;
        RECT 2.985 0.080 3.075 0.590 ;
        RECT 0.625 0.590 0.795 0.730 ;
        RECT 2.945 0.590 3.115 0.730 ;
    END
  END vss
  PIN zn
    DIRECTION OUTPUT ;
    USE SIGNAL ;
    ANTENNADIFFAREA 0.335000 ;
    PORT
      LAYER MET1 ;
        RECT 0.045 0.840 0.215 0.980 ;
        RECT 0.085 0.980 0.175 2.020 ;
        RECT 0.045 2.020 0.215 2.160 ;
    END
  END zn
  OBS
    LAYER MET1 ;
      RECT 2.655 0.170 2.825 0.195 ;
      RECT 1.535 0.195 2.825 0.285 ;
      RECT 1.535 0.285 1.625 0.615 ;
      RECT 2.655 0.285 2.825 0.310 ;
      RECT 1.205 0.590 1.375 0.615 ;
      RECT 1.785 0.590 1.955 0.730 ;
      RECT 2.365 0.590 2.535 0.615 ;
      RECT 3.525 0.590 3.695 0.730 ;
      RECT 1.205 0.615 1.625 0.705 ;
      RECT 2.115 0.615 2.535 0.705 ;
      RECT 1.205 0.705 1.375 0.730 ;
      RECT 2.115 0.705 2.205 2.495 ;
      RECT 2.365 0.705 2.535 0.730 ;
      RECT 1.825 0.730 1.915 1.285 ;
      RECT 3.565 0.730 3.655 1.285 ;
      RECT 1.205 1.260 1.375 1.285 ;
      RECT 2.655 1.260 2.825 1.285 ;
      RECT 1.205 1.285 1.915 1.375 ;
      RECT 2.655 1.285 3.655 1.375 ;
      RECT 1.205 1.375 1.375 1.400 ;
      RECT 1.825 1.375 1.915 2.470 ;
      RECT 2.655 1.375 2.825 1.400 ;
      RECT 3.565 1.375 3.655 2.470 ;
      RECT 2.655 2.020 2.825 2.160 ;
      RECT 2.695 2.160 2.785 2.915 ;
      RECT 1.205 2.470 1.375 2.495 ;
      RECT 1.785 2.470 1.955 2.610 ;
      RECT 2.365 2.470 2.535 2.495 ;
      RECT 3.525 2.470 3.695 2.495 ;
      RECT 1.205 2.495 1.625 2.585 ;
      RECT 2.115 2.495 2.535 2.585 ;
      RECT 3.275 2.495 3.695 2.585 ;
      RECT 1.205 2.585 1.375 2.610 ;
      RECT 1.535 2.585 1.625 2.915 ;
      RECT 2.365 2.585 2.535 2.610 ;
      RECT 3.275 2.585 3.365 2.890 ;
      RECT 3.525 2.585 3.695 2.610 ;
      RECT 3.235 2.890 3.405 3.030 ;
      RECT 1.535 2.915 2.785 3.005 ;
  END
END ics55f_XNR2D1

MACRO ics55f_MUX2D1
  CLASS CORE ;
  FOREIGN ics55f_MUX2D1 ;
  ORIGIN 0.000 0.000 ;
  SIZE 4.600 BY 3.200 ;
  SYMMETRY X Y R90 ;
  SITE obssite ;
  PIN i0
    DIRECTION INPUT ;
    USE SIGNAL ;
    ANTENNAGATEAREA 0.047100 ;
    PORT
      LAYER POLY ;
        RECT 2.130 0.445 2.190 1.535 ;
        RECT 2.075 1.535 2.245 1.705 ;
        RECT 2.130 1.705 2.190 2.755 ;
      LAYER MET1 ;
        RECT 2.075 1.550 2.245 1.690 ;
        RECT 2.115 1.690 2.205 2.135 ;
    END
  END i0
  PIN i1
    DIRECTION INPUT ;
    USE SIGNAL ;
    ANTENNAGATEAREA 0.060000 ;
    PORT
      LAYER POLY ;
        RECT 0.390 0.445 0.450 1.245 ;
        RECT 0.335 1.245 0.505 1.415 ;
        RECT 0.390 1.415 0.450 2.755 ;
      LAYER MET1 ;
        RECT 0.335 1.260 0.505 1.400 ;
        RECT 0.375 1.400 0.465 1.665 ;
    END
  END i1
  PIN s
    DIRECTION INPUT ;
    USE SIGNAL ;
    ANTENNAGATEAREA 0.060000 ;
    PORT
      LAYER POLY ;
        RECT 0.915 0.155 1.085 0.210 ;
        RECT 0.915 0.210 2.770 0.270 ;
        RECT 0.915 0.270 1.085 0.325 ;
        RECT 2.710 0.270 2.770 2.755 ;
        RECT 0.970 0.325 1.030 1.590 ;
        RECT 0.970 1.590 1.610 1.650 ;
        RECT 1.550 1.650 1.610 2.755 ;
      LAYER MET1 ;
        RECT 0.915 0.170 1.085 0.195 ;
        RECT 0.915 0.195 1.335 0.285 ;
        RECT 0.915 0.285 1.085 0.310 ;
    END
  END s
  PIN vdd
    DIRECTION INOUT ;
    USE POWER ;
    SHAPE ABUTMENT ;
    PORT
      LAYER MET1 ;
        RECT 0.045 2.470 0.215 2.610 ;
        RECT 2.365 2.470 2.535 2.610 ;
        RECT 4.105 2.470 4.275 2.610 ;
        RECT 0.085 2.610 0.175 3.120 ;
        RECT 2.405 2.610 2.495 3.120 ;
        RECT 4.145 2.610 4.235 3.120 ;
        RECT 0.000 3.120 4.600 3.280 ;
    END
  END vdd
  PIN vss
    DIRECTION INOUT ;
    USE GROUND ;
    SHAPE ABUTMENT ;
    PORT
      LAYER MET1 ;
        RECT 0.000 -0.080 4.600 0.080 ;
        RECT 0.085 0.080 0.175 0.590 ;
        RECT 2.405 0.080 2.495 0.590 ;
        RECT 4.145 0.080 4.235 0.590 ;
        RECT 0.045 0.590 0.215 0.730 ;
        RECT 2.365 0.590 2.535 0.730 ;
        RECT 4.105 0.590 4.275 0.730 ;
    END
  END vss
  PIN z
    DIRECTION OUTPUT ;
    USE SIGNAL ;
    ANTENNADIFFAREA 0.274700 ;
    PORT
      LAYER MET1 ;
        RECT 3.525 0.840 3.695 0.980 ;
        RECT 3.565 0.980 3.655 2.470 ;
        RECT 3.525 2.470 3.695 2.610 ;
    END
  END z
  OBS
    LAYER MET1 ;
      RECT 1.205 0.590 1.375 0.615 ;
      RECT 1.785 0.590 1.955 0.615 ;
      RECT 2.945 0.590 3.115 0.730 ;
      RECT 0.955 0.615 1.375 0.705 ;
      RECT 1.535 0.615 1.955 0.705 ;
      RECT 0.955 0.705 1.045 2.495 ;
      RECT 1.205 0.705 1.375 0.730 ;
      RECT 1.535 0.705 1.625 2.495 ;
      RECT 1.785 0.705 1.955 0.730 ;
      RECT 2.985 0.730 3.075 1.285 ;
      RECT 0.625 0.840 0.795 0.980 ;
      RECT 0.665 0.980 0.755 2.020 ;
      RECT 1.205 1.260 1.375 1.400 ;
      RECT 1.785 1.260 1.955 1.285 ;
      RECT 1.785 1.285 3.075 1.375 ;
      RECT 1.785 1.375 1.955 1.400 ;
      RECT 2.695 1.375 2.785 2.495 ;
      RECT 1.245 1.400 1.335 2.020 ;
      RECT 0.625 2.020 0.795 2.160 ;
      RECT 1.205 2.020 1.375 2.160 ;
      RECT 1.205 2.470 1.375 2.495 ;
      RECT 1.785 2.470 1.955 2.495 ;
      RECT 2.945 2.470 3.115 2.495 ;
      RECT 0.955 2.495 1.375 2.585 ;
      RECT 1.535 2.495 1.955 2.585 ;
      RECT 2.695 2.495 3.115 2.585 ;
      RECT 1.205 2.585 1.375 2.610 ;
      RECT 1.785 2.585 1.955 2.610 ;
      RECT 2.945 2.585 3.115 2.610 ;
      RECT 1.245 2.610 1.335 2.890 ;
      RECT 1.205 2.890 1.375 3.030 ;
  END
END ics55f_MUX2D1

MACRO ics55f_DFQD1
  CLASS CORE ;
  FOREIGN ics55f_DFQD1 ;
  ORIGIN 0.000 0.000 ;
  SIZE 8.600 BY 3.200 ;
  SYMMETRY X Y R90 ;
  SITE obssite ;
  PIN cp
    DIRECTION INPUT ;
    USE SIGNAL ;
    ANTENNAGATEAREA 0.060000 ;
    PORT
      LAYER POLY ;
        RECT 0.390 0.445 0.450 1.245 ;
        RECT 0.335 1.245 0.505 1.415 ;
        RECT 0.390 1.415 0.450 2.755 ;
      LAYER MET1 ;
        RECT 0.335 1.260 0.505 1.400 ;
        RECT 0.375 1.400 0.465 1.665 ;
    END
  END cp
  PIN d
    DIRECTION INPUT ;
    USE SIGNAL ;
    ANTENNAGATEAREA 0.036600 ;
    PORT
      LAYER POLY ;
        RECT 2.710 0.445 2.770 1.245 ;
        RECT 2.655 1.245 2.825 1.415 ;
        RECT 2.710 1.415 2.770 2.755 ;
      LAYER MET1 ;
        RECT 2.655 1.260 2.825 1.400 ;
        RECT 2.695 1.400 2.785 1.665 ;
    END
  END d
  PIN q
    DIRECTION OUTPUT ;
    USE SIGNAL ;
    ANTENNADIFFAREA 0.335000 ;
    PORT
      LAYER POLY ;
        RECT 7.295 0.825 7.465 0.995 ;
        RECT 7.350 0.995 7.410 2.005 ;
        RECT 7.295 2.005 7.465 2.175 ;
      LAYER MET1 ;
        RECT 7.295 0.840 7.465 0.865 ;
        RECT 7.585 0.840 7.755 0.865 ;
        RECT 7.295 0.865 7.755 0.955 ;
        RECT 7.295 0.955 7.465 0.980 ;
        RECT 7.585 0.955 7.755 0.980 ;
        RECT 7.295 2.020 7.465 2.045 ;
        RECT 7.585 2.020 7.755 2.045 ;
        RECT 7.295 2.045 7.755 2.135 ;
        RECT 7.295 2.135 7.465 2.160 ;
        RECT 7.585 2.135 7.755 2.160 ;
    END
  END q
  PIN vdd
    DIRECTION INOUT ;
    USE POWER ;
    SHAPE ABUTMENT ;
    PORT
      LAYER MET1 ;
        RECT 0.625 2.470 0.795 2.610 ;
        RECT 1.785 2.470 1.955 2.610 ;
        RECT 4.105 2.470 4.275 2.610 ;
        RECT 6.425 2.470 6.595 2.610 ;
        RECT 8.165 2.470 8.335 2.610 ;
        RECT 0.665 2.610 0.755 3.120 ;
        RECT 1.825 2.610 1.915 3.120 ;
        RECT 4.145 2.610 4.235 3.120 ;
        RECT 6.465 2.610 6.555 3.120 ;
        RECT 8.205 2.610 8.295 3.120 ;
        RECT 0.000 3.120 8.600 3.280 ;
    END
  END vdd
  PIN vss
    DIRECTION INOUT ;
    USE GROUND ;
    SHAPE ABUTMENT ;
    PORT
      LAYER MET1 ;
        RECT 0.000 -0.080 8.600 0.080 ;
        RECT 0.665 0.080 0.755 0.590 ;
        RECT 1.825 0.080 1.915 0.590 ;
        RECT 4.145 0.080 4.235 0.590 ;
        RECT 6.465 0.080 6.555 0.590 ;
        RECT 8.205 0.080 8.295 0.590 ;
        RECT 0.625 0.590 0.795 0.730 ;
        RECT 1.785 0.590 1.955 0.730 ;
        RECT 4.105 0.590 4.275 0.730 ;
        RECT 6.425 0.590 6.595 0.730 ;
        RECT 8.165 0.590 8.335 0.730 ;
    END
  END vss
  OBS
    LAYER MET1 ;
      RECT 0.045 0.170 0.215 0.310 ;
      RECT 6.135 0.170 6.305 0.195 ;
      RECT 7.005 0.170 7.175 0.310 ;
      RECT 5.305 0.195 6.305 0.285 ;
      RECT 5.305 0.285 5.395 0.590 ;
      RECT 6.135 0.285 6.305 0.310 ;
      RECT 0.085 0.310 0.175 0.590 ;
      RECT 7.045 0.310 7.135 0.590 ;
      RECT 0.045 0.590 0.215 0.730 ;
      RECT 2.945 0.590 3.115 0.615 ;
      RECT 4.685 0.590 4.855 0.730 ;
      RECT 5.265 0.590 5.435 0.730 ;
      RECT 7.005 0.590 7.175 0.730 ;
      RECT 2.945 0.615 3.365 0.705 ;
      RECT 2.945 0.705 3.115 0.730 ;
      RECT 3.275 0.705 3.365 2.045 ;
      RECT 4.725 0.730 4.815 0.865 ;
      RECT 5.305 0.730 5.395 2.470 ;
      RECT 0.045 0.840 0.215 0.980 ;
      RECT 1.205 0.840 1.375 0.980 ;
      RECT 3.815 0.840 3.985 0.865 ;
      RECT 7.005 0.840 7.175 0.980 ;
      RECT 3.815 0.865 4.815 0.955 ;
      RECT 3.815 0.955 3.985 0.980 ;
      RECT 4.725 0.955 4.815 2.470 ;
      RECT 0.085 0.980 0.175 2.020 ;
      RECT 1.245 0.980 1.335 2.020 ;
      RECT 3.855 0.980 3.945 1.550 ;
      RECT 7.045 0.980 7.135 1.285 ;
      RECT 4.395 1.260 4.565 1.400 ;
      RECT 6.135 1.260 6.305 1.285 ;
      RECT 6.135 1.285 7.135 1.375 ;
      RECT 6.135 1.375 6.305 1.400 ;
      RECT 7.045 1.375 7.135 1.575 ;
      RECT 4.435 1.400 4.525 2.020 ;
      RECT 3.815 1.550 3.985 1.690 ;
      RECT 6.135 1.550 6.305 1.575 ;
      RECT 7.875 1.550 8.045 1.575 ;
      RECT 6.135 1.575 8.045 1.665 ;
      RECT 6.135 1.665 6.305 1.690 ;
      RECT 7.045 1.665 7.135 2.020 ;
      RECT 7.875 1.665 8.045 1.690 ;
      RECT 0.045 2.020 0.215 2.160 ;
      RECT 1.205 2.020 1.375 2.045 ;
      RECT 1.495 2.020 1.665 2.045 ;
      RECT 2.945 2.020 3.115 2.045 ;
      RECT 4.395 2.020 4.565 2.045 ;
      RECT 7.005 2.020 7.175 2.160 ;
      RECT 1.205 2.045 3.115 2.135 ;
      RECT 3.275 2.045 4.565 2.135 ;
      RECT 1.205 2.135 1.375 2.160 ;
      RECT 1.495 2.135 1.665 2.160 ;
      RECT 2.945 2.135 3.115 2.160 ;
      RECT 3.275 2.135 3.365 2.495 ;
      RECT 4.395 2.135 4.565 2.160 ;
      RECT 2.945 2.470 3.115 2.495 ;
      RECT 4.685 2.470 4.855 2.610 ;
      RECT 5.265 2.470 5.435 2.610 ;
      RECT 2.945 2.495 3.365 2.585 ;
      RECT 2.945 2.585 3.115 2.610 ;
  END
END ics55f_DFQD1

MACRO ics55f_DFCNQD1
  CLASS CORE ;
  FOREIGN ics55f_DFCNQD1 ;
  ORIGIN 0.000 0.000 ;
  SIZE 10.400 BY 3.200 ;
  SYMMETRY X Y R90 ;
  SITE obssite ;
  PIN cdn
    DIRECTION INPUT ;
    USE SIGNAL ;
    ANTENNAGATEAREA 0.073800 ;
    PORT
      LAYER POLY ;
        RECT 4.450 0.445 4.510 2.060 ;
        RECT 7.930 0.445 7.990 1.590 ;
        RECT 5.265 1.535 5.435 1.590 ;
        RECT 5.265 1.590 7.990 1.650 ;
        RECT 5.265 1.650 5.435 1.705 ;
        RECT 7.930 1.650 7.990 2.755 ;
        RECT 5.320 1.705 5.380 2.060 ;
        RECT 4.450 2.060 5.380 2.120 ;
        RECT 5.030 2.120 5.090 2.755 ;
      LAYER MET1 ;
        RECT 5.265 1.550 5.565 1.690 ;
    END
  END cdn
  PIN cp
    DIRECTION INPUT ;
    USE SIGNAL ;
    ANTENNAGATEAREA 0.030000 ;
    PORT
      LAYER POLY ;
        RECT 0.390 0.445 0.450 1.535 ;
        RECT 0.335 1.535 0.505 1.705 ;
        RECT 0.390 1.705 0.450 2.755 ;
      LAYER MET1 ;
        RECT 0.335 1.550 0.505 1.575 ;
        RECT 0.335 1.575 0.755 1.665 ;
        RECT 0.335 1.665 0.505 1.690 ;
    END
  END cp
  PIN d
    DIRECTION INPUT ;
    USE SIGNAL ;
    ANTENNAGATEAREA 0.038400 ;
    PORT
      LAYER POLY ;
        RECT 2.710 0.445 2.770 1.245 ;
        RECT 2.655 1.245 2.825 1.415 ;
        RECT 2.710 1.415 2.770 2.755 ;
      LAYER MET1 ;
        RECT 2.655 1.260 2.825 1.400 ;
        RECT 2.695 1.400 2.785 1.665 ;
    END
  END d
  PIN q
    DIRECTION OUTPUT ;
    USE SIGNAL ;
    ANTENNADIFFAREA 0.335000 ;
    PORT
      LAYER MET1 ;
        RECT 9.905 0.840 10.075 0.980 ;
        RECT 9.945 0.980 10.035 1.575 ;
        RECT 9.365 1.575 10.035 1.665 ;
        RECT 9.365 1.665 9.455 2.020 ;
        RECT 9.325 2.020 9.495 2.160 ;
    END
  END q
  PIN vdd
    DIRECTION INOUT ;
    USE POWER ;
    SHAPE ABUTMENT ;
    PORT
      LAYER MET1 ;
        RECT 0.625 2.470 0.795 2.610 ;
        RECT 1.785 2.470 1.955 2.610 ;
        RECT 4.105 2.470 4.275 2.610 ;
        RECT 5.265 2.470 5.435 2.610 ;
        RECT 7.585 2.470 7.755 2.610 ;
        RECT 8.745 2.470 8.915 2.610 ;
        RECT 0.665 2.610 0.755 3.120 ;
        RECT 1.825 2.610 1.915 3.120 ;
        RECT 4.145 2.610 4.235 3.120 ;
        RECT 5.305 2.610 5.395 3.120 ;
        RECT 7.625 2.610 7.715 3.120 ;
        RECT 8.785 2.610 8.875 3.120 ;
        RECT 0.000 3.120 10.400 3.280 ;
    END
  END vdd
  PIN vss
    DIRECTION INOUT ;
    USE GROUND ;
    SHAPE ABUTMENT ;
    PORT
      LAYER MET1 ;
        RECT 0.000 -0.080 10.400 0.080 ;
        RECT 0.665 0.080 0.755 0.590 ;
        RECT 1.825 0.080 1.915 0.590 ;
        RECT 4.725 0.080 4.815 0.590 ;
        RECT 7.625 0.080 7.715 0.590 ;
        RECT 9.365 0.080 9.455 0.590 ;
        RECT 0.625 0.590 0.795 0.730 ;
        RECT 1.785 0.590 1.955 0.730 ;
        RECT 4.685 0.590 4.855 0.730 ;
        RECT 7.585 0.590 7.755 0.730 ;
        RECT 9.325 0.590 9.495 0.730 ;
    END
  END vss
  OBS
    LAYER MET1 ;
      RECT 1.205 0.170 1.375 0.310 ;
      RECT 5.265 0.170 5.435 0.310 ;
      RECT 5.555 0.170 5.725 0.310 ;
      RECT 5.845 0.170 6.015 0.310 ;
      RECT 1.245 0.310 1.335 0.590 ;
      RECT 5.305 0.310 5.395 0.590 ;
      RECT 5.595 0.310 5.685 0.865 ;
      RECT 5.885 0.310 5.975 0.590 ;
      RECT 0.045 0.590 0.215 0.730 ;
      RECT 1.205 0.590 1.375 0.730 ;
      RECT 2.945 0.590 3.115 0.730 ;
      RECT 5.265 0.590 5.435 0.730 ;
      RECT 5.845 0.590 6.015 0.730 ;
      RECT 6.425 0.590 6.595 0.615 ;
      RECT 7.005 0.590 7.175 0.615 ;
      RECT 6.425 0.615 7.175 0.705 ;
      RECT 6.425 0.705 6.595 0.730 ;
      RECT 7.005 0.705 7.175 0.730 ;
      RECT 0.085 0.730 0.175 1.285 ;
      RECT 2.985 0.730 3.075 1.575 ;
      RECT 3.235 0.840 3.405 0.865 ;
      RECT 6.135 0.840 6.305 0.980 ;
      RECT 8.745 0.840 8.915 0.980 ;
      RECT 3.235 0.865 5.685 0.955 ;
      RECT 3.235 0.955 3.405 0.980 ;
      RECT 6.175 0.980 6.265 2.890 ;
      RECT 8.785 0.980 8.875 1.285 ;
      RECT 2.075 1.260 2.245 1.285 ;
      RECT 3.815 1.260 3.985 1.285 ;
      RECT 6.715 1.260 6.885 1.400 ;
      RECT 7.295 1.260 7.465 1.285 ;
      RECT 9.615 1.260 9.785 1.285 ;
      RECT 0.085 1.285 2.245 1.375 ;
      RECT 3.815 1.285 5.975 1.375 ;
      RECT 7.295 1.285 9.785 1.375 ;
      RECT 0.085 1.375 0.175 2.045 ;
      RECT 2.075 1.375 2.245 1.400 ;
      RECT 3.815 1.375 3.985 1.400 ;
      RECT 5.885 1.375 5.975 2.470 ;
      RECT 7.295 1.375 7.465 1.400 ;
      RECT 8.205 1.375 8.295 2.470 ;
      RECT 8.785 1.375 8.875 1.575 ;
      RECT 9.615 1.375 9.785 1.400 ;
      RECT 6.755 1.400 6.845 2.020 ;
      RECT 7.335 1.400 7.425 2.020 ;
      RECT 4.975 1.550 5.145 1.575 ;
      RECT 9.035 1.550 9.205 1.575 ;
      RECT 2.985 1.575 5.145 1.665 ;
      RECT 8.785 1.575 9.205 1.665 ;
      RECT 2.985 1.665 3.075 2.470 ;
      RECT 4.975 1.665 5.145 1.690 ;
      RECT 9.035 1.665 9.205 1.690 ;
      RECT 5.015 1.690 5.105 2.045 ;
      RECT 0.915 2.020 1.085 2.045 ;
      RECT 5.555 2.020 5.725 2.045 ;
      RECT 6.715 2.020 6.885 2.160 ;
      RECT 7.295 2.020 7.465 2.160 ;
      RECT 0.085 2.045 1.085 2.135 ;
      RECT 3.565 2.045 4.815 2.135 ;
      RECT 5.015 2.045 5.725 2.135 ;
      RECT 0.085 2.135 0.175 2.470 ;
      RECT 0.915 2.135 1.085 2.160 ;
      RECT 3.565 2.135 3.655 2.470 ;
      RECT 4.725 2.135 4.815 2.470 ;
      RECT 5.555 2.135 5.725 2.160 ;
      RECT 0.045 2.470 0.215 2.610 ;
      RECT 1.205 2.470 1.375 2.495 ;
      RECT 1.495 2.470 1.665 2.495 ;
      RECT 2.945 2.470 3.115 2.610 ;
      RECT 3.525 2.470 3.695 2.610 ;
      RECT 4.685 2.470 4.855 2.610 ;
      RECT 5.845 2.470 6.015 2.610 ;
      RECT 6.425 2.470 6.595 2.610 ;
      RECT 8.165 2.470 8.335 2.610 ;
      RECT 1.205 2.495 1.665 2.585 ;
      RECT 1.205 2.585 1.375 2.610 ;
      RECT 1.495 2.585 1.665 2.610 ;
      RECT 6.465 2.610 6.555 2.890 ;
      RECT 6.135 2.890 6.305 3.030 ;
      RECT 6.425 2.890 6.595 3.030 ;
  END
END ics55f_DFCNQD1

MACRO ics55f_TIEH
  CLASS CORE TIEHIGH ;
  FOREIGN ics55f_TIEH ;
  ORIGIN 0.000 0.000 ;
  SIZE 1.000 BY 3.200 ;
  SYMMETRY X Y R90 ;
  SITE obssite ;
  PIN vdd
    DIRECTION INOUT ;
    USE POWER ;
    SHAPE ABUTMENT ;
    PORT
      LAYER MET1 ;
        RECT 0.625 2.470 0.795 2.610 ;
        RECT 0.665 2.610 0.755 3.120 ;
        RECT 0.000 3.120 1.000 3.280 ;
    END
  END vdd
  PIN vss
    DIRECTION INOUT ;
    USE GROUND ;
    SHAPE ABUTMENT ;
    PORT
      LAYER MET1 ;
        RECT 0.000 -0.080 1.000 0.080 ;
        RECT 0.665 0.080 0.755 0.590 ;
        RECT 0.625 0.590 0.795 0.730 ;
    END
  END vss
  PIN z
    DIRECTION OUTPUT ;
    USE SIGNAL ;
    ANTENNADIFFAREA 0.201000 ;
    PORT
      LAYER MET1 ;
        RECT 0.085 2.045 0.175 2.470 ;
        RECT 0.045 2.470 0.215 2.610 ;
        RECT 0.085 2.610 0.175 3.005 ;
    END
  END z
  OBS
    LAYER MET1 ;
      RECT 0.335 0.170 0.505 0.310 ;
      RECT 0.375 0.310 0.465 0.615 ;
      RECT 0.045 0.590 0.215 0.615 ;
      RECT 0.045 0.615 0.465 0.705 ;
      RECT 0.045 0.705 0.215 0.730 ;
  END
END ics55f_TIEH

MACRO ics55f_TIEL
  CLASS CORE TIELOW ;
  FOREIGN ics55f_TIEL ;
  ORIGIN 0.000 0.000 ;
  SIZE 1.000 BY 3.200 ;
  SYMMETRY X Y R90 ;
  SITE obssite ;
  PIN vdd
    DIRECTION INOUT ;
    USE POWER ;
    SHAPE ABUTMENT ;
    PORT
      LAYER MET1 ;
        RECT 0.625 2.470 0.795 2.610 ;
        RECT 0.665 2.610 0.755 3.120 ;
        RECT 0.000 3.120 1.000 3.280 ;
    END
  END vdd
  PIN vss
    DIRECTION INOUT ;
    USE GROUND ;
    SHAPE ABUTMENT ;
    PORT
      LAYER MET1 ;
        RECT 0.000 -0.080 1.000 0.080 ;
        RECT 0.665 0.080 0.755 0.590 ;
        RECT 0.625 0.590 0.795 0.730 ;
    END
  END vss
  PIN zn
    DIRECTION OUTPUT ;
    USE SIGNAL ;
    ANTENNADIFFAREA 0.134000 ;
    PORT
      LAYER MET1 ;
        RECT 0.085 0.235 0.175 0.705 ;
        RECT -0.020 0.840 0.280 0.980 ;
    END
  END zn
  OBS
    LAYER MET1 ;
      RECT 0.045 1.550 0.215 1.690 ;
      RECT 0.085 1.690 0.175 2.020 ;
      RECT 0.045 2.020 0.215 2.160 ;
  END
END ics55f_TIEL

MACRO ics55f_FILL1
  CLASS CORE SPACER ;
  FOREIGN ics55f_FILL1 ;
  ORIGIN 0.000 0.000 ;
  SIZE 0.200 BY 3.200 ;
  SYMMETRY X Y R90 ;
  SITE obssite ;
  PIN vdd
    DIRECTION INOUT ;
    USE POWER ;
    SHAPE ABUTMENT ;
    PORT
      LAYER MET1 ;
        RECT 0.000 3.120 0.200 3.280 ;
    END
  END vdd
  PIN vss
    DIRECTION INOUT ;
    USE GROUND ;
    SHAPE ABUTMENT ;
    PORT
      LAYER MET1 ;
        RECT 0.000 -0.080 0.200 0.080 ;
    END
  END vss
END ics55f_FILL1

MACRO ics55f_FILL2
  CLASS CORE SPACER ;
  FOREIGN ics55f_FILL2 ;
  ORIGIN 0.000 0.000 ;
  SIZE 0.400 BY 3.200 ;
  SYMMETRY X Y R90 ;
  SITE obssite ;
  PIN vdd
    DIRECTION INOUT ;
    USE POWER ;
    SHAPE ABUTMENT ;
    PORT
      LAYER MET1 ;
        RECT 0.000 3.120 0.400 3.280 ;
    END
  END vdd
  PIN vss
    DIRECTION INOUT ;
    USE GROUND ;
    SHAPE ABUTMENT ;
    PORT
      LAYER MET1 ;
        RECT 0.000 -0.080 0.400 0.080 ;
    END
  END vss
END ics55f_FILL2

MACRO ics55f_FILL4
  CLASS CORE SPACER ;
  FOREIGN ics55f_FILL4 ;
  ORIGIN 0.000 0.000 ;
  SIZE 0.800 BY 3.200 ;
  SYMMETRY X Y R90 ;
  SITE obssite ;
  PIN vdd
    DIRECTION INOUT ;
    USE POWER ;
    SHAPE ABUTMENT ;
    PORT
      LAYER MET1 ;
        RECT 0.000 3.120 0.800 3.280 ;
    END
  END vdd
  PIN vss
    DIRECTION INOUT ;
    USE GROUND ;
    SHAPE ABUTMENT ;
    PORT
      LAYER MET1 ;
        RECT 0.000 -0.080 0.800 0.080 ;
    END
  END vss
END ics55f_FILL4

MACRO ics55f_FILL8
  CLASS CORE SPACER ;
  FOREIGN ics55f_FILL8 ;
  ORIGIN 0.000 0.000 ;
  SIZE 1.600 BY 3.200 ;
  SYMMETRY X Y R90 ;
  SITE obssite ;
  PIN vdd
    DIRECTION INOUT ;
    USE POWER ;
    SHAPE ABUTMENT ;
    PORT
      LAYER MET1 ;
        RECT 0.000 3.120 1.600 3.280 ;
    END
  END vdd
  PIN vss
    DIRECTION INOUT ;
    USE GROUND ;
    SHAPE ABUTMENT ;
    PORT
      LAYER MET1 ;
        RECT 0.000 -0.080 1.600 0.080 ;
    END
  END vss
END ics55f_FILL8

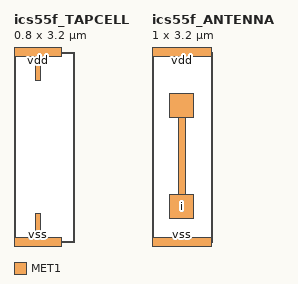
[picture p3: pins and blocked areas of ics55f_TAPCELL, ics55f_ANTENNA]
MACRO ics55f_TAPCELL
  CLASS CORE WELLTAP ;
  FOREIGN ics55f_TAPCELL ;
  ORIGIN 0.000 0.000 ;
  SIZE 0.800 BY 3.200 ;
  SYMMETRY X Y R90 ;
  SITE obssite ;
  PIN vdd
    DIRECTION INOUT ;
    USE POWER ;
    SHAPE ABUTMENT ;
    PORT
      LAYER MET1 ;
        RECT 0.355 2.715 0.445 3.120 ;
        RECT 0.000 3.120 0.800 3.280 ;
    END
  END vdd
  PIN vss
    DIRECTION INOUT ;
    USE GROUND ;
    SHAPE ABUTMENT ;
    PORT
      LAYER MET1 ;
        RECT 0.000 -0.080 0.800 0.080 ;
        RECT 0.355 0.080 0.445 0.485 ;
    END
  END vss
END ics55f_TAPCELL

MACRO ics55f_ANTENNA
  CLASS CORE ANTENNACELL ;
  FOREIGN ics55f_ANTENNA ;
  ORIGIN 0.000 0.000 ;
  SIZE 1.000 BY 3.200 ;
  SYMMETRY X Y R90 ;
  SITE obssite ;
  PIN i
    DIRECTION INPUT ;
    USE SIGNAL ;
    PORT
      LAYER MET1 ;
        RECT 0.300 0.400 0.700 0.800 ;
        RECT 0.440 0.800 0.560 2.100 ;
        RECT 0.300 2.100 0.700 2.500 ;
    END
  END i
  PIN vdd
    DIRECTION INOUT ;
    USE POWER ;
    SHAPE ABUTMENT ;
    PORT
      LAYER MET1 ;
        RECT 0.000 3.120 1.000 3.280 ;
    END
  END vdd
  PIN vss
    DIRECTION INOUT ;
    USE GROUND ;
    SHAPE ABUTMENT ;
    PORT
      LAYER MET1 ;
        RECT 0.000 -0.080 1.000 0.080 ;
    END
  END vss
END ics55f_ANTENNA

END LIBRARY
